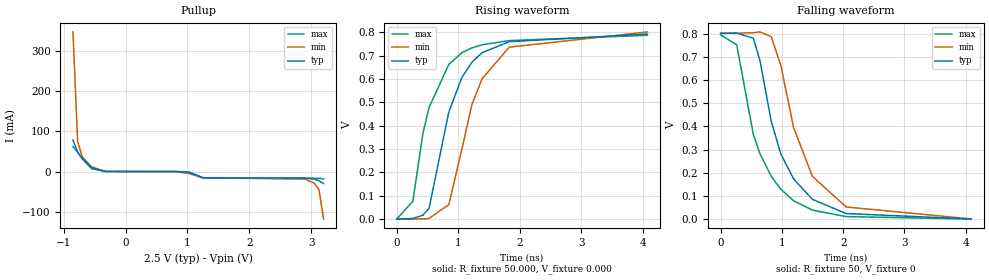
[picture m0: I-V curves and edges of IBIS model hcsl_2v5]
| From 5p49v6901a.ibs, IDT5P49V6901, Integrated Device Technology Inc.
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|   Model HCSL_2V5
[Model]   hcsl_2v5
Model_type   Open_source
Polarity   Non-Inverting
|   typ   min   max
C_comp   2pF   1.5pF   2.5pF
Vmeas = 0.43V
Rref = 50
Cref = 0
Vref = 0V
|   typ   min   max
[Voltage range]   2.5V   2.375V   2.625V
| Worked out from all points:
|   rising waveform, R_fixture 50.000, V_fixture 0.000: 20-80 % time 484ps typ, 517ps min, 446ps max; typ from 0 V to 0.793 V
|   falling waveform, R_fixture 50, V_fixture 0: 20-80 % time 553ps typ, 561ps min, 545ps max; typ from 0.802 V to 0 V
[Pullup]
|Voltage   I (typ)   I (min)   I (max)
|Note, modeling breaks down at 250mA and above.  This is well beyond the functional   |
|operating range of the device.  Should this scenario occur, catastrophic failure and   |
|possible damage to the device and/or board is of higher concern than the I-V curve   |
|behavior.  The IBIS checker will flag currents in excess of 10A with warnings.  Lines   |
|with currents in excess of 0.35 A have been commented out.  The points still remain|
|available to the user if the user desires to use them.   |
|-2.50000e+00   4.18820e+02   3.62831e+02   5.13988e+02
|-2.42500e+00   3.98060e+02   3.45526e+02   4.87489e+02
|-2.35000e+00   3.77301e+02   3.28221e+02   4.60992e+02
|-2.27500e+00   3.56544e+02   3.10918e+02   4.34497e+02
|-2.20000e+00   3.35789e+02   2.93617e+02   4.08003e+02
|-2.12500e+00   3.15035e+02   2.76317e+02   3.81510e+02
|-2.05000e+00   2.94284e+02   2.59020e+02   3.55019e+02
|-1.97500e+00   2.73534e+02   2.41725e+02   3.28531e+02
|-1.90000e+00   2.52787e+02   2.24432e+02   3.02045e+02
|-1.82500e+00   2.32043e+02   2.07143e+02   2.75561e+02
|-1.75000e+00   2.11303e+02   1.89857e+02   2.49081e+02
|-1.67500e+00   1.90567e+02   1.72576e+02   2.22604e+02
|-1.60000e+00   1.69836e+02   1.55301e+02   1.96133e+02
|-1.52500e+00   1.49113e+02   1.38033e+02   1.69668e+02
|-1.45000e+00   1.28399e+02   1.20775e+02   1.43213e+02
|-1.37500e+00   1.07699e+02   1.03530e+02   1.16771e+02
|-1.30000e+00   8.70206e+01   8.63041e+01   9.03510e+01
|-1.22500e+00   6.63754e+01   6.91071e+01   6.39696e+01
|-1.15000e+00   4.57798e+01   5.19493e+01   3.76540e+01
|-1.07500e+00   2.52424e+01   3.48371e+01   1.14171e+01
|-1.00000e+00   5.41544e+00   1.77617e+01   4.43906e-01
|-9.25000e-01   3.83575e-01   3.12352e+00   8.37580e-02
-850mV    78.22mA    346.9mA    62mA
-775mV    48.65mA    75.2mA     48.13mA
-700mV    32.45mA    36.4mA     31.33mA
-550mV    9.462mA    11.62mA    7.118mA
-325mV    90.12uA    245.7uA    48.7uA
800mV     13.39uA    -86.15uA   39.9uA
1.025V    -2.499mA   -4.68mA    -734.3uA
1.25V     -15.62mA   -15.74mA   -15.3mA
2.9V      -16.6mA    -18.65mA   -16.36mA
3.05V     -18.62mA   -28.95mA   -16.45mA
3.125V    -22.86mA   -44.46mA   -16.7mA
3.2V      -30mA      -118mA     -18.33mA
| 3.27500e+00   -3.99973e-02   -7.03299e-01   -2.35496e-02
| 3.35000e+00   -6.07334e-02   -6.06546e+00   -3.27185e-02
| 3.42500e+00   -2.19666e-01   -1.69043e+01   -4.43357e-02
| 3.50000e+00   -2.40671e+00   -2.77743e+01   -5.63861e-02
| 3.57500e+00   -1.44320e+01   -3.86883e+01   -8.58002e-02
| 3.65000e+00   -2.74894e+01   -4.96441e+01   -6.38151e-01
| 3.72500e+00   -4.06046e+01   -6.06330e+01   -1.12031e+01
| 3.80000e+00   -5.37689e+01   -7.16520e+01   -2.79002e+01
| 3.87500e+00   -6.69730e+01   -8.26854e+01   -4.46763e+01
| 3.95000e+00   -8.02022e+01   -9.37284e+01   -6.15101e+01
| 4.02500e+00   -9.34439e+01   -1.04778e+02   -7.83881e+01
| 4.10000e+00   -1.06694e+02   -1.15833e+02   -9.52824e+01
| 4.17500e+00   -1.19949e+02   -1.26892e+02   -1.12186e+02
| 4.25000e+00   -1.33208e+02   -1.37953e+02   -1.29096e+02
| 4.32500e+00   -1.46471e+02   -1.49017e+02   -1.46010e+02
| 4.40000e+00   -1.59735e+02   -1.60082e+02   -1.62927e+02
| 4.47500e+00   -1.73001e+02   -1.71149e+02   -1.79845e+02
| 4.55000e+00   -1.86268e+02   -1.82218e+02   -1.96764e+02
| 4.62500e+00   -1.99537e+02   -1.93287e+02   -2.13683e+02
| 4.70000e+00   -2.12805e+02   -2.04356e+02   -2.30604e+02
| 4.77500e+00   -2.26075e+02   -2.15427e+02   -2.47524e+02
| 4.85000e+00   -2.39344e+02   -2.26498e+02   -2.64445e+02
| 4.92500e+00   -2.52615e+02   -2.37569e+02   -2.81365e+02
| 5.00000e+00   -2.65885e+02   -2.48641e+02   -2.98285e+02
[Ramp]
|   typ   min   max
dV/dt_r   0.475/0.484n   0.476/0.517n   0.472/0.445n
dV/dt_f   0.484/0.553n   0.484/0.561n   0.48/0.544n
[Rising Waveform]
R_fixture = 50.000
V_fixture = 0.000
C_fixture = 0.000
|  time   V(typ)   V(min)   V(max)
|   0.0000S   28.5793nV   0.0000V   29.5095nV
|   2.3462pS   31.0738nV   2.4061nV   32.1138nV
|   4.2108pS   32.4562nV   3.7577nV   33.5300nV
|   4.4420pS   32.5955nV   3.8628nV   33.7030nV
|   7.3280pS   33.9249nV   5.0972nV   35.0261nV
|   13.0019pS   33.3378nV   5.1447nV   34.2093nV
|   13.6485pS   33.2990nV   5.3782nV   34.1032nV
|   25.3304pS   33.1176nV   11.3216nV   29.4633nV
|   37.2341pS   57.3045nV   49.6739nV   53.8500nV
|   44.0306pS   97.1087nV   71.5711nV   87.6653nV
|   53.3133pS   152.7020nV   131.3706nV   143.8910nV
|   60.9180pS   203.5620nV   167.5757nV   195.7820nV
|   70.0000pS   237.8080nV   183.2777nV   249.4730nV
|   72.5284pS   220.6020nV   141.6206nV   248.8590nV
|   76.7544pS   153.5140nV   41.9220nV   222.0950nV
|   78.9623pS   95.1189nV   -15.6849nV   195.6210nV
|   80.9324pS   41.4279nV   -87.5339nV   173.5600nV
|   88.5157pS   -148.9140nV   -304.8954nV   128.5840nV
|   93.1838pS   -107.4520nV   -417.7216nV   227.6830nV
|  101.7760pS   777.1820pV   -211.9427nV   448.4860nV
|  109.9270pS   525.8680nV   186.3348nV   871.3740nV
|  117.1110pS   1.0438uV   773.2547nV   1.2050uV
|  122.3270pS   1.4411uV   1.2347uV   1.3277uV
|  131.3260pS   1.7549uV   1.8623uV   1.4319uV
|  140.6930pS   1.7963uV   2.1994uV   1.1210uV
|  148.1030pS   1.4259uV   1.7308uV   152.7890nV
|  153.9250pS   164.2910nV   1.2348uV   -914.7540nV
|  167.5560pS   -4.6287uV   -2.8398uV   -6.3502uV
|  177.3450pS   -9.4856uV   -8.4278uV   -12.4768uV
|  187.4150pS   -16.4560uV   -14.4705uV   -19.4102uV
|  204.4310pS   -28.2434uV   -26.3360uV   -32.5150uV
|  216.2830pS   -36.4630uV   -34.0899uV   -40.9609uV
|  229.2050pS   -44.6579uV   -42.3338uV   -48.5451uV
|  243.7590pS   -52.7527uV   -50.0817uV   -54.4610uV
|  252.2000pS   -55.5125uV   -54.5752uV   -51.7248uV
|  259.2920pS   -55.5394uV   -56.2824uV   -47.0232uV
|  264.7700pS   -53.1141uV   -57.6011uV   -42.7650uV
|  275.8110pS   -47.2652uV   -54.9867uV   -35.0982uV
|  281.5050pS   -43.8840uV   -53.1142uV   -32.1211uV
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0s        28.58nV    0V         29.51nV
261.4ps   2.114mV    -121.9uV   76.3mV
424.2ps   16.32mV    209.7uV    366.2mV
525ps     45.74mV    2.661mV    477.8mV
846.1ps   458.7mV    61.44mV    662.7mV
1.06ns    607.4mV    300.7mV    713.4mV
1.221ns   671.6mV    489.5mV    733.6mV
1.387ns   713.2mV    601.4mV    747.2mV
1.83ns    760.5mV    737mV      765.2mV
4.077ns   793.1mV    802.2mV    787.8mV
[Falling Waveform]
R_fixture = 50
V_fixture = 0
C_fixture = 0.0p
| Time   typ   min   max
| 0.00000e+00   8.01941e-01   8.02942e-01   7.95708e-01
| 5.33133e-11   8.01942e-01   8.02943e-01   7.95709e-01
| 7.67544e-11   8.01942e-01   8.02943e-01   7.95710e-01
| 8.37028e-11   8.01941e-01   8.02941e-01   7.95708e-01
| 9.31838e-11   8.01937e-01   8.02938e-01   7.95705e-01
| 1.01776e-10   8.01934e-01   8.02934e-01   7.95701e-01
| 1.09927e-10   8.01931e-01   8.02931e-01   7.95697e-01
| 1.17111e-10   8.01928e-01   8.02929e-01   7.95694e-01
| 1.22327e-10   8.01927e-01   8.02928e-01   7.95692e-01
| 1.31326e-10   8.01924e-01   8.02925e-01   7.95689e-01
| 1.40693e-10   8.01921e-01   8.02923e-01   7.95686e-01
| 1.48103e-10   8.01919e-01   8.02921e-01   7.95682e-01
| 1.60973e-10   8.01912e-01   8.02915e-01   7.95674e-01
| 1.69673e-10   8.01905e-01   8.02909e-01   7.95668e-01
| 1.85089e-10   8.01891e-01   8.02896e-01   7.95652e-01
| 1.97157e-10   8.01879e-01   8.02884e-01   7.95640e-01
| 2.07668e-10   8.01870e-01   8.02874e-01   7.95631e-01
| 2.23901e-10   8.01858e-01   8.02862e-01   7.95619e-01
| 2.37017e-10   8.01850e-01   8.02854e-01   7.95618e-01
| 2.49663e-10   8.01846e-01   8.02848e-01   7.95623e-01
| 2.54056e-10   8.01848e-01   8.02847e-01   7.95626e-01
| 2.64416e-10   8.01854e-01   8.02847e-01   7.95641e-01
| 2.69451e-10   8.01859e-01   8.02849e-01   7.95648e-01
| 2.79424e-10   8.01870e-01   8.02855e-01   7.95662e-01
| 2.85315e-10   8.01877e-01   8.02861e-01   7.95669e-01
| 2.93370e-10   8.01886e-01   8.02869e-01   7.95679e-01
| 3.05155e-10   8.01900e-01   8.02881e-01   7.95691e-01
| 3.18179e-10   8.01914e-01   8.02894e-01   7.95703e-01
| 3.25707e-10   8.01921e-01   8.02902e-01   7.95709e-01
| 3.36176e-10   8.01931e-01   8.02912e-01   7.95715e-01
| 3.51299e-10   8.01942e-01   8.02926e-01   7.95722e-01
| 3.66584e-10   8.01951e-01   8.02938e-01   7.95727e-01
| 3.74935e-10   8.01956e-01   8.02944e-01   7.95729e-01
| 4.00361e-10   8.01965e-01   8.02958e-01   7.95735e-01
| 4.15457e-10   8.01969e-01   8.02965e-01   7.95739e-01
| 4.25576e-10   8.01972e-01   8.02969e-01   7.95741e-01
| 4.34776e-10   8.01975e-01   8.02972e-01   7.95744e-01
| 4.47976e-10   8.01979e-01   8.02977e-01   7.95747e-01
| 4.57169e-10   8.01982e-01   8.02980e-01   7.95748e-01
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0s        801.9mV    802.9mV    795.7mV
262.4ps   803.4mV    802.8mV    752.9mV
533.6ps   781.3mV    804.8mV    365.9mV
642ps     685.2mV    808.3mV    282.1mV
824.6ps   423.9mV    788.2mV    185.4mV
981.2ps   281.9mV    664.9mV    129.3mV
1.191ns   173.3mV    395.2mV    79.15mV
1.496ns   85.61mV    185.1mV    38.68mV
2.047ns   23.91mV    52.3mV     10.76mV
4.089ns   342.4uV    600.6uV    216.2uV
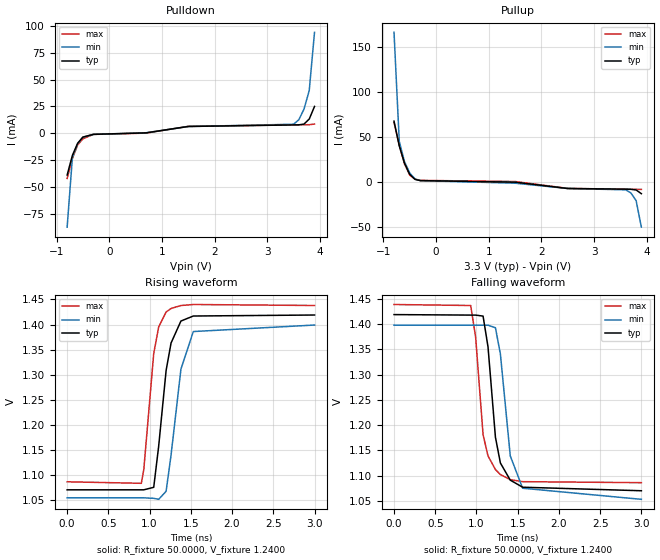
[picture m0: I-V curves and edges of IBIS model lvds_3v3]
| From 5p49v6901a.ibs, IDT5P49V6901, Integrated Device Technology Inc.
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[Model]   lvds_3v3
Model_type   Output
Polarity   Non-Inverting
|   typ   min   max
C_comp   2pF   1.5pF   2.5pF
Vmeas = 1.25V
Rref = 50
Cref = 2.0000pF
Vref = 1.25V
|   typ   min   max
[Voltage range]   3.3V   3.135V   3.465V
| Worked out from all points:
|   slope of the pulldown table from 0 to 0.495 V, typ, clamps not added: 1.35 kohm
|   slope of the pullup table from 0 to 0.495 V, typ, clamps not added: 2.31 kohm
|   rising waveform, R_fixture 50.0000, V_fixture 1.2400: 20-80 % time 141ps typ, 153ps min, 122ps max; typ from 1.07 V to 1.42 V
|   falling waveform, R_fixture 50.0000, V_fixture 1.2400: 20-80 % time 126ps typ, 138ps min, 116ps max; typ from 1.42 V to 1.07 V
[Pulldown]
|Voltage   I (typ)   I (min)   I (max)
|Note, modeling breaks down at 250mA and above.  This is well beyond the functional   |
|operating range of the device.  Should this scenario occur, catastrophic failure and   |
|possible damage to the device and/or board is of higher concern than the I-V curve   |
|behavior.  The IBIS checker will flag currents in excess of 10A with warnings.  Lines   |
|with currents in excess of 0.35 A have been commented out.  The points still remain|
|available to the user if the user desires to use them.   |
|  -3.30   -0.4582kA   -0.3985kA   -0.5583kA
|  -3.20   -0.4380kA   -0.3813kA   -0.5333kA
|  -3.10   -0.4179kA   -0.3641kA   -0.5083kA
|  -3.00   -0.3978kA   -0.3469kA   -0.4833kA
|  -2.90   -0.3776kA   -0.3297kA   -0.4583kA
|  -2.80   -0.3575kA   -0.3125kA   -0.4333kA
|  -2.70   -0.3374kA   -0.2954kA   -0.4083kA
|  -2.60   -0.3173kA   -0.2782kA   -0.3833kA
|  -2.50   -0.2972kA   -0.2611kA   -0.3584kA
|  -2.40   -0.2771kA   -0.2439kA   -0.3334kA
|  -2.30   -0.2570kA   -0.2268kA   -0.3084kA
|  -2.20   -0.2370kA   -0.2097kA   -0.2835kA
|  -2.10   -0.2169kA   -0.1926kA   -0.2585kA
|  -2.00   -0.1969kA   -0.1756kA   -0.2336kA
|  -1.90   -0.1769kA   -0.1585kA   -0.2087kA
|  -1.80   -0.1569kA   -0.1415kA   -0.1838kA
|  -1.70   -0.1370kA   -0.1246kA   -0.1590kA
|  -1.60   -0.1172kA   -0.1077kA   -0.1342kA
|  -1.50   -97.4500A   -91.0200A   -0.1095kA
|  -1.40   -77.8400A   -74.4200A   -84.9400A
|  -1.30   -58.5000A   -58.1100A   -60.6000A
|  -1.20   -39.6600A   -42.2500A   -36.8000A
|  -1.10   -21.5900A   -27.0400A   -13.9400A
|  -1.00   -4.1450A   -12.3600A   -0.3834A
|  -0.90   -0.1592A   -1.1570A   -64.1900mA
-800mV    -38.8mA    -87.29mA   -41.95mA
-700mV    -20.46mA   -22.38mA   -23.42mA
-600mV    -9.163mA   -9.47mA    -10.79mA
-500mV    -3.444mA   -3.582mA   -5.079mA
-300mV    -919.6uA   -946.5uA   -970.7uA
700mV     447.6uA    578.5uA    248.3uA
1.5V      6.423mA    6.34mA     6.53mA
3.5V      7.848mA    8.487mA    7.912mA
3.6V      7.922mA    12.55mA    7.955mA
3.7V      8.616mA    22.48mA    7.999mA
3.8V      13.34mA    39.88mA    8.057mA
3.9V      25.05mA    94.03mA    8.65mA
|  4.00   43.9800mA   0.8865A   14.2600mA
|  4.10   70.9600mA   13.8800A   28.7000mA
|  4.20   0.2968A   36.6400A   51.5700mA
|  4.30   8.8350A   59.4700A   74.7900mA
|  4.40   36.1700A   82.3700A   0.1211A
|  4.50   63.5900A   0.1053kA   3.5170A
|  4.60   91.1100A   0.1283kA   36.4900A
|  4.70   0.1187kA   0.1513kA   71.5800A
|  4.80   0.1463kA   0.1743kA   0.1067kA
|  4.90   0.1739kA   0.1974kA   0.1420kA
|  5.00   0.2015kA   0.2204kA   0.1773kA
|  5.10   0.2292kA   0.2435kA   0.2126kA
|  5.20   0.2569kA   0.2666kA   0.2479kA
|  5.30   0.2845kA   0.2896kA   0.2832kA
|  5.40   0.3122kA   0.3127kA   0.3185kA
|  5.50   0.3399kA   0.3358kA   0.3538kA
|  5.60   0.3676kA   0.3589kA   0.3891kA
|  5.70   0.3952kA   0.3819kA   0.4245kA
|  5.80   0.4229kA   0.4050kA   0.4598kA
|  5.90   0.4506kA   0.4281kA   0.4951kA
|  6.00   0.4783kA   0.4512kA   0.5305kA
|  6.10   0.5060kA   0.4743kA   0.5658kA
|  6.20   0.5337kA   0.4974kA   0.6012kA
|  6.30   0.5614kA   0.5205kA   0.6365kA
|  6.40   0.5891kA   0.5436kA   0.6719kA
|  6.50   0.6168kA   0.5667kA   0.7072kA
|  6.60   0.6445kA   0.5898kA   0.7425kA
[Pullup]
|Voltage   I (typ)   I (min)   I (max)
|Note, modeling breaks down at 250mA and above.  This is well beyond the functional   |
|operating range of the device.  Should this scenario occur, catastrophic failure and   |
|possible damage to the device and/or board is of higher concern than the I-V curve   |
|behavior.  The IBIS checker will flag currents in excess of 10A with warnings.  Lines   |
|with currents in excess of 0.35 A have been commented out.  The points still remain|
|available to the user if the user desires to use them.   |
|  -3.30   0.6445kA   0.5517kA   0.8009kA
|  -3.20   0.6168kA   0.5286kA   0.7655kA
|  -3.10   0.5891kA   0.5055kA   0.7302kA
|  -3.00   0.5614kA   0.4824kA   0.6948kA
|  -2.90   0.5337kA   0.4593kA   0.6595kA
|  -2.80   0.5060kA   0.4362kA   0.6241kA
|  -2.70   0.4783kA   0.4131kA   0.5888kA
|  -2.60   0.4506kA   0.3900kA   0.5535kA
|  -2.50   0.4229kA   0.3669kA   0.5181kA
|  -2.40   0.3953kA   0.3439kA   0.4828kA
|  -2.30   0.3676kA   0.3208kA   0.4474kA
|  -2.20   0.3399kA   0.2977kA   0.4121kA
|  -2.10   0.3122kA   0.2746kA   0.3768kA
|  -2.00   0.2845kA   0.2516kA   0.3415kA
|  -1.90   0.2569kA   0.2285kA   0.3061kA
|  -1.80   0.2292kA   0.2055kA   0.2708kA
|  -1.70   0.2016kA   0.1824kA   0.2355kA
|  -1.60   0.1739kA   0.1594kA   0.2002kA
|  -1.50   0.1463kA   0.1363kA   0.1649kA
|  -1.40   0.1187kA   0.1133kA   0.1296kA
|  -1.30   91.1200A   90.4000A   94.4500A
|  -1.20   63.5900A   67.4700A   59.2800A
|  -1.10   36.1700A   44.6200A   24.2500A
|  -1.00   8.8330A   21.8400A   0.7339A
|  -0.90   0.2942A   2.5180A   91.8900mA
-800mV    67.29mA    165.8mA    65.83mA
-700mV    39.75mA    44.68mA    40.36mA
-600mV    20.42mA    22.1mA     19.56mA
-500mV    8.108mA    9.559mA    7.259mA
-400mV    2.573mA    3.091mA    2.828mA
-300mV    1.267mA    1.258mA    1.499mA
1.5V      -484.3uA   -1.606mA   262.2uA
2.5V      -7.49mA    -7.515mA   -7.37mA
3.6V      -8.243mA   -8.947mA   -8.321mA
3.7V      -8.348mA   -12.35mA   -8.379mA
3.8V      -9.122mA   -20.94mA   -8.436mA
3.9V      -13.29mA   -50.39mA   -8.517mA
|  4.00   -23.0400mA   -0.4276A   -9.2430mA
|  4.10   -39.5300mA   -7.2910A   -14.5500mA
|  4.20   -0.1578A   -21.8600A   -27.4900mA
|  4.30   -4.1410A   -36.8500A   -44.1800mA
|  4.40   -21.5800A   -52.4900A   -76.1600mA
|  4.50   -39.6500A   -68.6700A   -1.6140A
|  4.60   -58.4900A   -85.1800A   -21.8200A
|  4.70   -77.8300A   -0.1018kA   -45.0300A
|  4.80   -97.4400A   -0.1187kA   -69.0600A
|  4.90   -0.1172kA   -0.1356kA   -93.5000A
|  5.00   -0.1370kA   -0.1526kA   -0.1181kA
|  5.10   -0.1569kA   -0.1696kA   -0.1428kA
|  5.20   -0.1769kA   -0.1866kA   -0.1677kA
|  5.30   -0.1969kA   -0.2037kA   -0.1925kA
|  5.40   -0.2169kA   -0.2208kA   -0.2174kA
|  5.50   -0.2370kA   -0.2379kA   -0.2423kA
|  5.60   -0.2570kA   -0.2550kA   -0.2672kA
|  5.70   -0.2771kA   -0.2722kA   -0.2922kA
|  5.80   -0.2972kA   -0.2893kA   -0.3171kA
|  5.90   -0.3173kA   -0.3065kA   -0.3421kA
|  6.00   -0.3374kA   -0.3237kA   -0.3671kA
|  6.10   -0.3575kA   -0.3409kA   -0.3921kA
|  6.20   -0.3776kA   -0.3580kA   -0.4170kA
|  6.30   -0.3977kA   -0.3752kA   -0.4420kA
|  6.40   -0.4179kA   -0.3924kA   -0.4670kA
|  6.50   -0.4380kA   -0.4096kA   -0.4920kA
|  6.60   -0.4581kA   -0.4268kA   -0.5170kA
[Ramp]
|   typ   min   max
dV/dt_r   0.21/0.14n   0.21/0.15n   0.22/0.128n
dV/dt_f   0.21/0.12n   0.21/0.14n   0.21/0.11n
R_load =   50
[Rising Waveform]
R_fixture= 50.0000
V_fixture= 1.2400
V_fixture_min= 1.2200
V_fixture_max= 1.2600
C_fixture = 0.000
|  time   V(typ)   V(min)   V(max)
0s        1.07V      1.054V     1.086V
900ps     1.07V      1.054V     1.083V
930ps     1.07V      1.054V     1.111V
1.05ns    1.075V     1.053V     1.342V
1.11ns    1.157V     1.051V     1.395V
1.2ns     1.308V     1.067V     1.425V
1.26ns    1.363V     1.139V     1.432V
1.38ns    1.407V     1.311V     1.438V
1.53ns    1.417V     1.386V     1.44V
3ns       1.419V     1.399V     1.438V
[Falling Waveform]
R_fixture= 50.0000
V_fixture= 1.2400
V_fixture_min= 1.2200
V_fixture_max= 1.2600
C_fixture = 0.000
|  time   V(typ)   V(min)   V(max)
0s        1.419V     1.398V     1.439V
930ps     1.418V     1.398V     1.437V
990ps     1.418V     1.398V     1.374V
1.08ns    1.416V     1.398V     1.181V
1.14ns    1.355V     1.398V     1.139V
1.23ns    1.176V     1.393V     1.112V
1.29ns    1.125V     1.341V     1.102V
1.41ns    1.091V     1.139V     1.092V
1.56ns    1.077V     1.075V     1.088V
3ns       1.07V      1.053V     1.086V
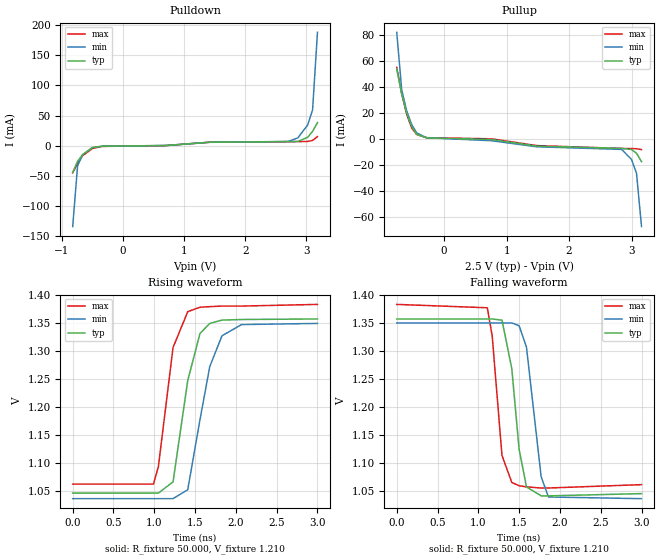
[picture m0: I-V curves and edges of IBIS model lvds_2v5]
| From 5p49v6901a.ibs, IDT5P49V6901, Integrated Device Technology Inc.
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[Model]   lvds_2v5
Model_type   Output
Polarity   Non-Inverting
|   typ   min   max
C_comp   2pF   1.5pF   2.5pF
Vmeas = 1.2V
Rref = 50
Cref = 2.0000pF
Vref = 1.2V
|   typ   min   max
[Voltage range]   2.5V   2.375V   2.625V
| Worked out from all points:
|   slope of the pulldown table from 0 to 0.375 V, typ, clamps not added: 2.21 kohm
|   slope of the pullup table from 0 to 0.375 V, typ, clamps not added: 2.23 kohm
|   rising waveform, R_fixture 50.000, V_fixture 1.210: 20-80 % time 196ps typ, 229ps min, 168ps max; typ from 1.05 V to 1.36 V
|   falling waveform, R_fixture 50.000, V_fixture 1.210: 20-80 % time 123ps typ, 144ps min, 107ps max; typ from 1.36 V to 1.05 V
[Pulldown]
|Voltage   I (typ)   I (min)   I (max)
|Note, modeling breaks down at 250mA and above.  This is well beyond the functional   |
|operating range of the device.  Should this scenario occur, catastrophic failure and   |
|possible damage to the device and/or board is of higher concern than the I-V curve   |
|behavior.  The IBIS checker will flag currents in excess of 10A with warnings.  Lines   |
|with currents in excess of 0.35 A have been commented out.  The points still remain|
|available to the user if the user desires to use them.   |
|  -2.50   -0.2972kA   -0.2611kA   -0.3583kA
|  -2.42   -0.2811kA   -0.2473kA   -0.3384kA
|  -2.34   -0.2651kA   -0.2336kA   -0.3184kA
|  -2.26   -0.2490kA   -0.2200kA   -0.2984kA
|  -2.18   -0.2330kA   -0.2063kA   -0.2785kA
|  -2.10   -0.2169kA   -0.1926kA   -0.2585kA
|  -2.02   -0.2009kA   -0.1790kA   -0.2386kA
|  -1.94   -0.1849kA   -0.1653kA   -0.2187kA
|  -1.86   -0.1689kA   -0.1517kA   -0.1987kA
|  -1.78   -0.1530kA   -0.1381kA   -0.1788kA
|  -1.70   -0.1370kA   -0.1246kA   -0.1590kA
|  -1.62   -0.1211kA   -0.1111kA   -0.1391kA
|  -1.54   -0.1053kA   -97.7000A   -0.1193kA
|  -1.46   -89.5800A   -84.3500A   -99.6600A
|  -1.38   -73.9400A   -71.1300A   -80.0400A
|  -1.30   -58.5000A   -58.1100A   -60.6000A
|  -1.22   -43.3700A   -45.3700A   -41.4900A
|  -1.14   -28.7200A   -33.0500A   -22.9700A
|  -1.06   -14.5400A   -21.1300A   -5.0190A
|  -0.98   -2.0260A   -9.4630A   -0.1959A
|  -0.90   -0.1583A   -1.1560A   -63.0600mA
-820mV    -44.36mA   -134mA     -44.88mA
-740mV    -26.03mA   -33.31mA   -29.63mA
-660mV    -14.78mA   -15.41mA   -16.81mA
-500mV    -3.134mA   -3.26mA    -4.727mA
-340mV    -851uA     -837.6uA   -1.156mA
700mV     355.5uA    317.2uA    190.7uA
1.42V     5.778mA    5.658mA    5.873mA
2.7V      6.77mA     7.054mA    6.772mA
2.86V     7.044mA    13.02mA    6.838mA
3.02V     13.95mA    34.37mA    7.04mA
3.1V      23.83mA    59.36mA    8.71mA
3.18V     38.32mA    188mA      15.18mA
|  3.26   57.3300mA   1.5990A   27.3600mA
|  3.34   93.9700mA   13.8800A   45.0100mA
|  3.42   0.5398A   32.0900A   64.8000mA
|  3.50   8.8330A   50.3300A   82.1900mA
|  3.58   30.6900A   68.6200A   0.1675A
|  3.66   52.6100A   86.9500A   3.5160A
|  3.74   74.5900A   0.1053kA   29.4900A
|  3.82   96.6300A   0.1237kA   57.5200A
|  3.90   0.1187kA   0.1421kA   85.6400A
|  3.98   0.1407kA   0.1605kA   0.1138kA
|  4.06   0.1628kA   0.1789kA   0.1420kA
|  4.14   0.1850kA   0.1974kA   0.1702kA
|  4.22   0.2071kA   0.2158kA   0.1984kA
|  4.30   0.2292kA   0.2343kA   0.2267kA
|  4.38   0.2513kA   0.2527kA   0.2549kA
|  4.46   0.2735kA   0.2712kA   0.2832kA
|  4.54   0.2956kA   0.2896kA   0.3114kA
|  4.62   0.3177kA   0.3081kA   0.3397kA
|  4.70   0.3399kA   0.3265kA   0.3679kA
|  4.78   0.3620kA   0.3450kA   0.3962kA
|  4.86   0.3842kA   0.3635kA   0.4245kA
|  4.94   0.4063kA   0.3819kA   0.4527kA
[Pullup]
|Voltage   I (typ)   I (min)   I (max)
|Note, modeling breaks down at 250mA and above.  This is well beyond the functional   |
|operating range of the device.  Should this scenario occur, catastrophic failure and   |
|possible damage to the device and/or board is of higher concern than the I-V curve   |
|behavior.  The IBIS checker will flag currents in excess of 10A with warnings.  Lines   |
|with currents in excess of 0.35 A have been commented out.  The points still remain|
|available to the user if the user desires to use them.   |
|  -2.44   0.4063kA   0.3531kA   0.4969kA
|  -2.36   0.3842kA   0.3346kA   0.4686kA
|  -2.28   0.3620kA   0.3162kA   0.4404kA
|  -2.20   0.3399kA   0.2977kA   0.4121kA
|  -2.12   0.3177kA   0.2793kA   0.3839kA
|  -2.04   0.2956kA   0.2608kA   0.3556kA
|  -1.96   0.2735kA   0.2423kA   0.3273kA
|  -1.88   0.2513kA   0.2239kA   0.2991kA
|  -1.80   0.2292kA   0.2055kA   0.2708kA
|  -1.72   0.2071kA   0.1870kA   0.2426kA
|  -1.64   0.1850kA   0.1686kA   0.2143kA
|  -1.56   0.1628kA   0.1502kA   0.1861kA
|  -1.48   0.1407kA   0.1317kA   0.1579kA
|  -1.40   0.1187kA   0.1133kA   0.1296kA
|  -1.32   96.6300A   94.9900A   0.1015kA
|  -1.24   74.5900A   76.6300A   73.3400A
|  -1.16   52.6100A   58.3200A   45.2500A
|  -1.08   30.6900A   40.0600A   17.2500A
|  -1.00   8.8320A   21.8400A   0.7328A
|  -0.92   0.5379A   4.6650A   0.1031A
|  -0.84   91.2400mA   0.4359A   73.7400mA
-760mV    53.9mA     82.15mA    55.12mA
-680mV    34.58mA    37.8mA     34.78mA
-600mV    19.77mA    21.51mA    18.87mA
-520mV    9.45mA     11.07mA    8.433mA
-440mV    3.57mA     4.621mA    3.384mA
-280mV    833.7uA    910.8uA    978.5uA
760mV     -398.9uA   -1.355mA   108.8uA
1.48V     -5.477mA   -6.046mA   -5.105mA
2.84V     -7.267mA   -8.038mA   -7.335mA
3V        -8.117mA   -15.75mA   -7.43mA
3.08V     -11.01mA   -26.46mA   -7.526mA
3.16V     -17.45mA   -67.48mA   -8.211mA
|  3.24   -27.5000mA   -0.4267A   -11.8300mA
|  3.32   -44.3500mA   -4.4170A   -20.4500mA
|  3.40   -0.1567A   -16.0000A   -33.0900mA
|  3.48   -2.0230A   -27.7800A   -46.5700mA
|  3.56   -14.5400A   -39.9200A   -75.1300mA
|  3.64   -28.7100A   -52.4900A   -0.6799A
|  3.72   -43.3600A   -65.4000A   -12.8100A
|  3.80   -58.4900A   -78.5400A   -30.9800A
|  3.88   -73.9400A   -91.8400A   -49.7800A
|  3.96   -89.5700A   -0.1052kA   -69.0600A
|  4.04   -0.1053kA   -0.1187kA   -88.5900A
|  4.12   -0.1211kA   -0.1322kA   -0.1082kA
|  4.20   -0.1370kA   -0.1458kA   -0.1280kA
|  4.28   -0.1529kA   -0.1594kA   -0.1478kA
|  4.36   -0.1689kA   -0.1730kA   -0.1676kA
|  4.44   -0.1849kA   -0.1866kA   -0.1875kA
|  4.52   -0.2009kA   -0.2003kA   -0.2074kA
|  4.60   -0.2169kA   -0.2140kA   -0.2273kA
|  4.68   -0.2329kA   -0.2276kA   -0.2473kA
|  4.76   -0.2490kA   -0.2413kA   -0.2672kA
|  4.84   -0.2650kA   -0.2550kA   -0.2872kA
|  4.92   -0.2811kA   -0.2688kA   -0.3071kA
|  5.00   -0.2972kA   -0.2825kA   -0.3271kA
[Ramp]
|   typ   min   max
dV/dt_r   0.19/0.198n   0.188/0.226n   0.188/0.167n
dV/dt_f   0.192/0.124n  0.194/0.147n   0.194/0.109n
R_load =   50
[Rising Waveform]
R_fixture = 50.000
V_fixture = 1.210
V_fixture_min = 1.190
V_fixture_max = 1.230
C_fixture = 0.000
|  time   V(typ)   V(min)   V(max)
0s        1.046V     1.036V     1.062V
990ps     1.046V     1.036V     1.062V
1.05ns    1.046V     1.036V     1.093V
1.23ns    1.066V     1.036V     1.306V
1.41ns    1.247V     1.052V     1.37V
1.56ns    1.331V     1.177V     1.378V
1.68ns    1.349V     1.272V     1.379V
1.83ns    1.355V     1.327V     1.38V
2.07ns    1.356V     1.347V     1.38V
3ns       1.357V     1.349V     1.383V
[Falling Waveform]
R_fixture = 50.000
V_fixture = 1.210
V_fixture_min = 1.190
V_fixture_max = 1.230
C_fixture = 0.000
|  time   V(typ)   V(min)   V(max)
0s        1.357V     1.35V      1.383V
1.11ns    1.357V     1.35V      1.377V
1.17ns    1.357V     1.35V      1.327V
1.29ns    1.355V     1.35V      1.114V
1.41ns    1.269V     1.35V      1.066V
1.5ns     1.125V     1.345V     1.06V
1.59ns    1.058V     1.307V     1.058V
1.77ns    1.042V     1.076V     1.056V
1.86ns    1.042V     1.04V      1.056V
3ns       1.046V     1.037V     1.062V
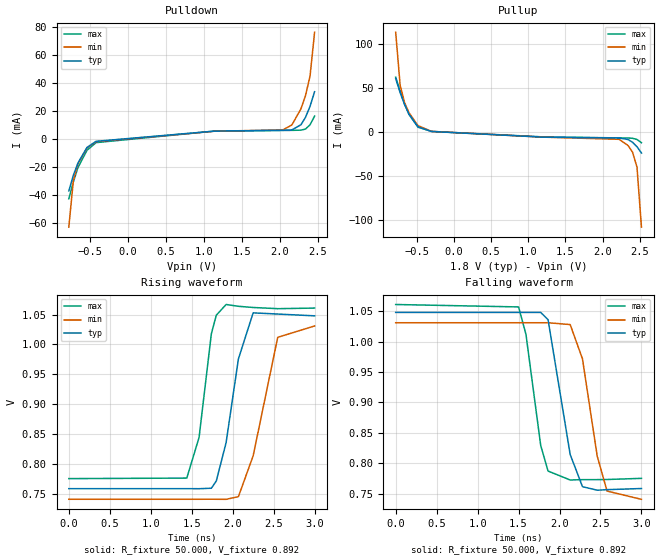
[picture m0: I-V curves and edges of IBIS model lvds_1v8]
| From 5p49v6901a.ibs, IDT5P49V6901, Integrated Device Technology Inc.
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[Model]   lvds_1v8
Model_type   Output
Polarity   Non-Inverting
|   typ   min   max
C_comp   2.0000pF   1.5000pF   2.5000pF
Vmeas =  0.9000V
Cref =   2.0000pF
Rref =   50.0000
Vref =   0.9000V
[Voltage Range]   1.8000V   1.7100V   1.8900V
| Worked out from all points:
|   slope of the pulldown table from 0 to 0.27 V, typ, clamps not added: 2.34 kohm
|   slope of the pullup table from 0 to 0.27 V, typ, clamps not added: 970 ohm
|   rising waveform, R_fixture 50.000, V_fixture 0.892: 20-80 % time 196ps typ, 247ps min, 153ps max; typ from 0.758 V to 1.05 V
|   falling waveform, R_fixture 50.000, V_fixture 0.892: 20-80 % time 183ps typ, 209ps min, 167ps max; typ from 1.05 V to 0.758 V
[Pulldown]
|Voltage   I(typ)   I(min)   I(max)
|Note, modeling breaks down at 250mA and above.  This is well beyond the functional   |
|operating range of the device.  Should this scenario occur, catastrophic failure and   |
|possible damage to the device and/or board is of higher concern than the I-V curve   |
|behavior.  The IBIS checker will flag currents in excess of 10A with warnings.  Lines   |
|with currents in excess of 0.35 A have been commented out.  The points still remain|
|available to the user if the user desires to use them.   |
|  -1.80   -0.1570kA   -0.1415kA   -0.1838kA
|  -1.74   -0.1450kA   -0.1314kA   -0.1689kA
|  -1.68   -0.1331kA   -0.1212kA   -0.1540kA
|  -1.62   -0.1211kA   -0.1111kA   -0.1392kA
|  -1.56   -0.1093kA   -0.1010kA   -0.1243kA
|  -1.50   -97.4600A   -91.0200A   -0.1095kA
|  -1.44   -85.6700A   -81.0400A   -94.7600A
|  -1.38   -73.9500A   -71.1400A   -80.0500A
|  -1.32   -62.3400A   -61.3500A   -65.4500A
|  -1.26   -50.8900A   -51.7000A   -51.0000A
|  -1.20   -39.6700A   -42.2600A   -36.8100A
|  -1.14   -28.7300A   -33.0500A   -22.9700A
|  -1.08   -18.0600A   -24.0800A   -9.4810A
|  -1.02   -7.5710A   -15.2800A   -0.8557A
|  -0.96   -1.0120A   -6.5720A   -0.1272A
|  -0.90   -0.1630A   -1.1600A   -69.8600mA
|  -0.84   -57.9600mA   -0.2220A   -54.8000mA
-780mV    -36.97mA   -62.75mA   -42.52mA
-720mV    -25.84mA   -29.43mA   -30.55mA
-660mV    -17.18mA   -17.75mA   -20.42mA
-540mV    -5.999mA   -6.454mA   -8.01mA
-420mV    -1.673mA   -1.886mA   -2.606mA
1.14V     5.583mA    5.506mA    5.585mA
2.04V     6.169mA    6.447mA    6.071mA
2.16V     6.42mA     9.934mA    6.116mA
2.28V     10.1mA     21.4mA     6.272mA
2.34V     15.35mA    30.81mA    7.057mA
2.4V      23.19mA    44.74mA    10.07mA
2.46V     33.62mA    75.87mA    16.26mA
|  2.52   46.6200mA   0.2091A   25.6700mA
|  2.58   62.2400mA   1.0230A   38.2000mA
|  2.64   93.2900mA   6.2830A   53.1600mA
|  2.70   0.2947A   19.5700A   67.2300mA
|  2.76   2.1550A   33.2200A   80.0900mA
|  2.82   14.2900A   46.9000A   0.1118A
|  2.88   30.6900A   60.6100A   0.4884A
|  2.94   47.1200A   74.3400A   6.9660A
|  3.00   63.5900A   88.1000A   27.7400A
|  3.06   80.0900A   0.1018kA   48.7500A
|  3.12   96.6200A   0.1156kA   69.8200A
|  3.18   0.1131kA   0.1294kA   90.9200A
|  3.24   0.1297kA   0.1432kA   0.1120kA
|  3.30   0.1463kA   0.1571kA   0.1332kA
|  3.36   0.1628kA   0.1709kA   0.1543kA
|  3.42   0.1794kA   0.1847kA   0.1755kA
|  3.48   0.1960kA   0.1985kA   0.1967kA
|  3.54   0.2126kA   0.2124kA   0.2178kA
|  3.60   0.2292kA   0.2262kA   0.2390kA
[Pullup]
|Voltage   I(typ)   I(min)   I(max)
|Note, modeling breaks down at 250mA and above.  This is well beyond the functional   |
|operating range of the device.  Should this scenario occur, catastrophic failure and   |
|possible damage to the device and/or board is of higher concern than the I-V curve   |
|behavior.  The IBIS checker will flag currents in excess of 10A with warnings.  Lines   |
|with currents in excess of 0.35 A have been commented out.  The points still remain|
|available to the user if the user desires to use them.   |
|  -1.80   0.2292kA   0.2055kA   0.2708kA
|  -1.74   0.2126kA   0.1916kA   0.2496kA
|  -1.68   0.1960kA   0.1778kA   0.2285kA
|  -1.62   0.1794kA   0.1640kA   0.2073kA
|  -1.56   0.1629kA   0.1502kA   0.1861kA
|  -1.50   0.1463kA   0.1363kA   0.1649kA
|  -1.44   0.1297kA   0.1225kA   0.1438kA
|  -1.38   0.1131kA   0.1087kA   0.1226kA
|  -1.32   96.6300A   94.9900A   0.1015kA
|  -1.26   80.1000A   81.2200A   80.3800A
|  -1.20   63.6000A   67.4700A   59.2900A
|  -1.14   47.1300A   53.7500A   38.2500A
|  -1.08   30.7000A   40.0600A   17.2600A
|  -1.02   14.2900A   26.3900A   1.7620A
|  -0.96   2.1570A   12.7400A   0.1929A
|  -0.90   0.2956A   2.5190A   94.2200mA
|  -0.84   93.1800mA   0.4375A   76.6300mA
-780mV    61.19mA    113.6mA    62.6mA
-720mV    44.92mA    53.18mA    46.62mA
-660mV    31.39mA    33.54mA    31.9mA
-600mV    20.42mA    22.01mA    20.1mA
-480mV    6.096mA    7.503mA    5.766mA
-300mV    903.7uA    986.2uA    939.5uA
1.2V      -5.591mA   -5.565mA   -5.291mA
2.22V     -6.556mA   -8.024mA   -6.442mA
2.34V     -8.282mA   -15.11mA   -6.542mA
2.4V      -11.35mA   -22.54mA   -6.848mA
2.46V     -16.49mA   -39.62mA   -8.208mA
2.52V     -23.64mA   -107.9mA   -11.96mA
|  2.58   -33.1500mA   -0.4889A   -18.6200mA
|  2.64   -52.3200mA   -2.8130A   -27.6700mA
|  2.70   -0.1556A   -10.9100A   -37.6600mA
|  2.76   -1.0030A   -19.6500A   -48.1000mA
|  2.82   -7.5600A   -28.5300A   -69.8800mA
|  2.88   -18.0500A   -37.6100A   -0.2588A
|  2.94   -28.7100A   -46.9400A   -3.1710A
|  3.00   -39.6500A   -56.4900A   -16.1700A
|  3.06   -50.8800A   -66.2100A   -29.8200A
|  3.12   -62.3300A   -76.0600A   -43.8400A
|  3.18   -73.9300A   -86.0100A   -58.1700A
|  3.24   -85.6500A   -96.0200A   -72.7100A
|  3.30   -97.4400A   -0.1060kA   -87.3700A
|  3.36   -0.1092kA   -0.1161kA   -0.1021kA
|  3.42   -0.1211kA   -0.1263kA   -0.1169kA
|  3.48   -0.1330kA   -0.1364kA   -0.1317kA
|  3.54   -0.1450kA   -0.1466kA   -0.1466kA
|  3.60   -0.1569kA   -0.1568kA   -0.1614kA
[Ramp]
|   typ   min   max
dV/dt_r   0.177/0.202n   0.180/0.241n   0.175/0.154n
dV/dt_f   0.181/0.183n   0.182/0.207n   0.177/0.169n
R_load =   50
[Rising Waveform]
R_fixture = 50.000
V_fixture = 0.892
V_fixture_min = 0.884
V_fixture_max = 0.895
C_fixture = 0.000
|  time   V(typ)   V(min)   V(max)
0s        758.4mV    740.6mV    775.2mV
1.44ns    758.4mV    740.6mV    776.1mV
1.59ns    758.3mV    740.6mV    844.2mV
1.74ns    759.1mV    740.7mV    1.018V
1.8ns     771.2mV    740.6mV    1.049V
1.92ns    835.5mV    740.5mV    1.067V
2.07ns    975.7mV    745mV      1.064V
2.25ns    1.053V     813.3mV    1.062V
2.55ns    1.051V     1.012V     1.06V
3ns       1.048V     1.031V     1.061V
[Falling Waveform]
R_fixture = 50.000
V_fixture = 0.892
V_fixture_min = 0.884
V_fixture_max = 0.895
C_fixture = 0.000
|  time   V(typ)   V(min)   V(max)
0s        1.048V     1.031V     1.061V
1.5ns     1.048V     1.031V     1.057V
1.59ns    1.048V     1.031V     1.012V
1.77ns    1.048V     1.031V     829.4mV
1.86ns    1.036V     1.031V     787.1mV
2.13ns    814.3mV    1.028V     772.4mV
2.28ns    761.4mV    971.6mV    773mV
2.46ns    755.6mV    811.6mV    773mV
2.58ns    756.5mV    754.2mV    773.2mV
3ns       758.4mV    740.6mV    775.1mV
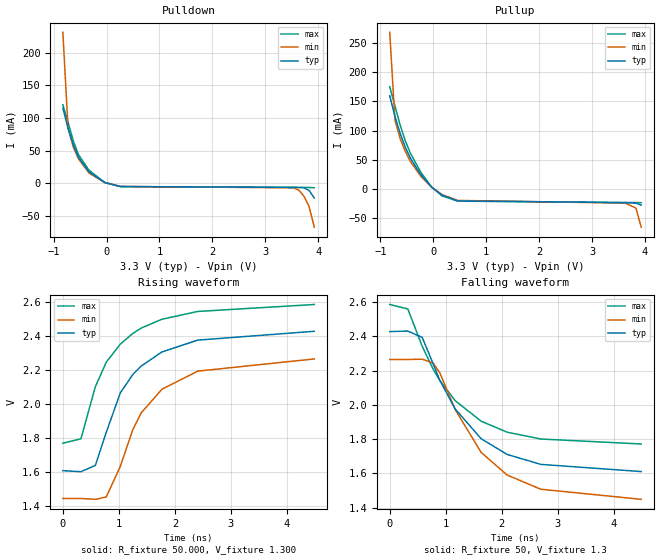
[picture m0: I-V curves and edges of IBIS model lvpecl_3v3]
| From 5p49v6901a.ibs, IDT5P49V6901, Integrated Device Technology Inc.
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[Model]   lvpecl_3v3
Model_type   Output_ECL
Polarity   Non-Inverting
|   typ   min   max
C_comp   2pF   1.5pF   2.5pF
Vmeas = 2.056V
Rref = 50
Cref = 0
Vref = 1.3V
|   typ   min   max
[Voltage range]   3.3V   3.135V   3.465V
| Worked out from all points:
|   rising waveform, R_fixture 50.000, V_fixture 1.300: 20-80 % time 834ps typ, 830ps min, 836ps max; typ from 1.61 V to 2.43 V
|   falling waveform, R_fixture 50, V_fixture 1.3: 20-80 % time 999ps typ, 993ps min, 1ns max; typ from 2.43 V to 1.61 V
[Pulldown]
|Voltage   I (typ)   I (min)   I (max)
|Note, modeling breaks down at 250mA and above.  This is well beyond the functional   |
|operating range of the device.  Should this scenario occur, catastrophic failure and   |
|possible damage to the device and/or board is of higher concern than the I-V curve   |
|behavior.  The IBIS checker will flag currents in excess of 10A with warnings.  Lines   |
|with currents in excess of 0.35 A have been commented out.  The points still remain|
|available to the user if the user desires to use them.   |
|-3.30000e+00   6.40494e+02   5.47645e+02   7.96897e+02
|-3.20100e+00   6.13071e+02   5.24782e+02   7.61900e+02
|-3.10200e+00   5.85650e+02   5.01920e+02   7.26904e+02
|-3.00300e+00   5.58231e+02   4.79060e+02   6.91910e+02
|-2.90400e+00   5.30813e+02   4.56202e+02   6.56917e+02
|-2.80500e+00   5.03397e+02   4.33346e+02   6.21926e+02
|-2.70600e+00   4.75983e+02   4.10491e+02   5.86937e+02
|-2.60700e+00   4.48571e+02   3.87639e+02   5.51949e+02
|-2.50800e+00   4.21161e+02   3.64788e+02   5.16964e+02
|-2.40900e+00   3.93753e+02   3.41940e+02   4.81981e+02
|-2.31000e+00   3.66348e+02   3.19095e+02   4.47000e+02
|-2.21100e+00   3.38946e+02   2.96252e+02   4.12022e+02
|-2.11200e+00   3.11546e+02   2.73413e+02   3.77047e+02
|-2.01300e+00   2.84151e+02   2.50577e+02   3.42075e+02
|-1.91400e+00   2.56759e+02   2.27746e+02   3.07106e+02
|-1.81500e+00   2.29372e+02   2.04920e+02   2.72143e+02
|-1.71600e+00   2.01992e+02   1.82101e+02   2.37185e+02
|-1.61700e+00   1.74621e+02   1.59291e+02   2.02236e+02
|-1.51800e+00   1.47261e+02   1.36492e+02   1.67297e+02
|-1.41900e+00   1.19919e+02   1.13712e+02   1.32374e+02
|-1.32000e+00   9.26062e+01   9.09588e+01   9.74818e+01
|-1.22100e+00   6.53450e+01   6.82506e+01   6.26476e+01
|-1.12200e+00   3.81712e+01   4.56115e+01   2.79291e+01
|-1.02300e+00   1.10897e+01   2.30475e+01   1.24893e+00
|-9.24000e-01   4.28238e-01   3.07704e+00   1.51169e-01
-825mV    115mA      231.1mA    120.2mA
-726mV    83.84mA    83.88mA    92.94mA
-627mV    58.71mA    55.32mA    64.83mA
-528mV    39.32mA    37.03mA    43.43mA
-330mV    17.18mA    15.49mA    19.86mA
-33mV     1.097mA    1.003mA    1.232mA
264mV     -5.075mA   -4.919mA   -5.211mA
3.531V    -6.413mA   -7.006mA   -6.366mA
3.63V     -6.463mA   -10.27mA   -6.395mA
3.729V    -6.98mA    -19.6mA    -6.428mA
3.828V    -10.89mA   -35.64mA   -6.475mA
3.927V    -22.76mA   -67.27mA   -6.885mA
| 4.02600e+00   -3.91581e-02   -5.27259e-01   -1.14674e-02
| 4.12500e+00   -5.19425e-02   -8.18306e+00   -2.73537e-02
| 4.22400e+00   -2.02189e-01   -2.24780e+01   -4.27150e-02
| 4.32300e+00   -5.36362e+00   -3.68412e+01   -5.54476e-02
| 4.42200e+00   -2.25356e+01   -5.12797e+01   -9.30834e-02
| 4.52100e+00   -3.98013e+01   -6.57781e+01   -2.39642e+00
| 4.62000e+00   -5.71554e+01   -8.03157e+01   -2.33704e+01
| 4.71900e+00   -7.45758e+01   -9.48736e+01   -4.54655e+01
| 4.81800e+00   -9.20266e+01   -1.09444e+02   -6.76653e+01
| 4.91700e+00   -1.09495e+02   -1.24024e+02   -8.99239e+01
| 5.01600e+00   -1.26974e+02   -1.38611e+02   -1.12205e+02
| 5.11500e+00   -1.44461e+02   -1.53203e+02   -1.34499e+02
| 5.21400e+00   -1.61953e+02   -1.67799e+02   -1.56802e+02
| 5.31300e+00   -1.79450e+02   -1.82398e+02   -1.79111e+02
| 5.41200e+00   -1.96951e+02   -1.97000e+02   -2.01425e+02
| 5.51100e+00   -2.14454e+02   -2.11605e+02   -2.23741e+02
| 5.61000e+00   -2.31959e+02   -2.26211e+02   -2.46061e+02
| 5.70900e+00   -2.49467e+02   -2.40819e+02   -2.68383e+02
| 5.80800e+00   -2.66976e+02   -2.55428e+02   -2.90706e+02
| 5.90700e+00   -2.84486e+02   -2.70039e+02   -3.13031e+02
| 6.00600e+00   -3.01998e+02   -2.84651e+02   -3.35358e+02
| 6.10500e+00   -3.19510e+02   -2.99263e+02   -3.57685e+02
| 6.20400e+00   -3.37024e+02   -3.13877e+02   -3.80013e+02
| 6.30300e+00   -3.54539e+02   -3.28492e+02   -4.02343e+02
| 6.40200e+00   -3.72054e+02   -3.43107e+02   -4.24672e+02
| 6.50100e+00   -3.89570e+02   -3.57723e+02   -4.47003e+02
| 6.60000e+00   -4.07087e+02   -3.72340e+02   -4.69334e+02
[Pullup]
|Voltage   I (typ)   I (min)   I (max)
|Note, modeling breaks down at 250mA and above.  This is well beyond the functional   |
|operating range of the device.  Should this scenario occur, catastrophic failure and   |
|possible damage to the device and/or board is of higher concern than the I-V curve   |
|behavior.  The IBIS checker will flag currents in excess of 10A with warnings.  Lines   |
|with currents in excess of 0.35 A have been commented out.  The points still remain|
|available to the user if the user desires to use them.   |
|-3.30000e+00   6.40605e+02   5.47748e+02   7.97022e+02
|-3.20100e+00   6.13181e+02   5.24884e+02   7.62023e+02
|-3.10200e+00   5.85758e+02   5.02020e+02   7.27026e+02
|-3.00300e+00   5.58337e+02   4.79159e+02   6.92030e+02
|-2.90400e+00   5.30918e+02   4.56298e+02   6.57035e+02
|-2.80500e+00   5.03500e+02   4.33440e+02   6.22043e+02
|-2.70600e+00   4.76084e+02   4.10583e+02   5.87053e+02
|-2.60700e+00   4.48670e+02   3.87728e+02   5.52065e+02
|-2.50800e+00   4.21258e+02   3.64876e+02   5.17079e+02
|-2.40900e+00   3.93848e+02   3.42025e+02   4.82094e+02
|-2.31000e+00   3.66441e+02   3.19177e+02   4.47112e+02
|-2.21100e+00   3.39037e+02   2.96332e+02   4.12132e+02
|-2.11200e+00   3.11636e+02   2.73490e+02   3.77154e+02
|-2.01300e+00   2.84238e+02   2.50652e+02   3.42180e+02
|-1.91400e+00   2.56844e+02   2.27819e+02   3.07209e+02
|-1.81500e+00   2.29455e+02   2.04990e+02   2.72242e+02
|-1.71600e+00   2.02072e+02   1.82169e+02   2.37281e+02
|-1.61700e+00   1.74697e+02   1.59355e+02   2.02328e+02
|-1.51800e+00   1.47334e+02   1.36554e+02   1.67385e+02
|-1.41900e+00   1.19989e+02   1.13771e+02   1.32459e+02
|-1.32000e+00   9.26721e+01   9.10147e+01   9.75623e+01
|-1.22100e+00   6.54071e+01   6.83032e+01   6.27235e+01
|-1.12200e+00   3.82293e+01   4.56605e+01   2.80002e+01
|-1.02300e+00   1.11435e+01   2.30929e+01   1.31491e+00
|-9.24000e-01   4.77531e-01   3.11851e+00   2.11788e-01
-825mV    159.6mA    268.6mA    175.1mA
-726mV    124mA      117.6mA    142.3mA
-627mV    94.83mA    85.82mA    109mA
-528mV    70.75mA    63.79mA    81.56mA
-429mV    51.56mA    46.15mA    60.02mA
-231mV    23.43mA    20.79mA    27.33mA
-33mV     2.74mA     2.456mA    3.148mA
165mV     -11.07mA   -10.12mA   -12.32mA
462mV     -20.83mA   -20.04mA   -21.28mA
3.63V     -23.8mA    -24.67mA   -23.68mA
3.828V    -24.79mA   -33.22mA   -23.76mA
3.927V    -28.03mA   -65.93mA   -23.85mA
| 4.02600e+00   -3.47525e-02   -5.27259e-01   -2.47658e-02
| 4.12500e+00   -5.19425e-02   -8.18306e+00   -2.89447e-02
| 4.22400e+00   -2.02189e-01   -2.24780e+01   -4.01130e-02
| 4.32300e+00   -5.36362e+00   -3.68412e+01   -5.54476e-02
| 4.42200e+00   -2.25356e+01   -5.12797e+01   -9.30837e-02
| 4.52100e+00   -3.98013e+01   -6.57781e+01   -2.39642e+00
| 4.62000e+00   -5.71554e+01   -8.03157e+01   -2.33704e+01
| 4.71900e+00   -7.45758e+01   -9.48736e+01   -4.54655e+01
| 4.81800e+00   -9.20266e+01   -1.09444e+02   -6.76653e+01
| 4.91700e+00   -1.09495e+02   -1.24024e+02   -8.99239e+01
| 5.01600e+00   -1.26974e+02   -1.38611e+02   -1.12205e+02
| 5.11500e+00   -1.44461e+02   -1.53203e+02   -1.34499e+02
| 5.21400e+00   -1.61953e+02   -1.67799e+02   -1.56802e+02
| 5.31300e+00   -1.79450e+02   -1.82398e+02   -1.79111e+02
| 5.41200e+00   -1.96951e+02   -1.97000e+02   -2.01425e+02
| 5.51100e+00   -2.14454e+02   -2.11605e+02   -2.23741e+02
| 5.61000e+00   -2.31959e+02   -2.26211e+02   -2.46061e+02
| 5.70900e+00   -2.49467e+02   -2.40819e+02   -2.68383e+02
| 5.80800e+00   -2.66976e+02   -2.55428e+02   -2.90706e+02
| 5.90700e+00   -2.84486e+02   -2.70039e+02   -3.13031e+02
| 6.00600e+00   -3.01998e+02   -2.84651e+02   -3.35358e+02
| 6.10500e+00   -3.19510e+02   -2.99263e+02   -3.57685e+02
| 6.20400e+00   -3.37024e+02   -3.13877e+02   -3.80013e+02
| 6.30300e+00   -3.54539e+02   -3.28492e+02   -4.02343e+02
| 6.40200e+00   -3.72054e+02   -3.43107e+02   -4.24672e+02
| 6.50100e+00   -3.89570e+02   -3.57723e+02   -4.47003e+02
| 6.60000e+00   -4.07087e+02   -3.72340e+02   -4.69334e+02
[Ramp]
|   typ   min   max
dV/dt_r   0.49/0.832n   0.49/0.83n   0.487/0.833n
dV/dt_f   0.492/0.998n   0.49/0.993n   0.492/1n
R_load =   50
[Rising Waveform]
R_fixture = 50.000
V_fixture = 1.300
V_fixture_min = 1.135
V_fixture_max = 1.465
C_fixture = 0.000
|  time   V(typ)   V(min)   V(max)
|   0.0000S   1.6060V   1.4423V   1.7683V
|   2.8363pS   1.6060V   1.4423V   1.7683V
|   5.2836pS   1.6060V   1.4423V   1.7683V
|   8.6600pS   1.6060V   1.4423V   1.7683V
|   15.6865pS   1.6060V   1.4423V   1.7683V
|   16.0689pS   1.6060V   1.4423V   1.7683V
|   29.7394pS   1.6060V   1.4423V   1.7683V
|   47.6708pS   1.6060V   1.4423V   1.7683V
|   50.2247pS   1.6060V   1.4423V   1.7683V
|   59.9282pS   1.6060V   1.4423V   1.7683V
|   70.0000pS   1.6060V   1.4423V   1.7683V
|   74.3341pS   1.6060V   1.4423V   1.7683V
|   79.7590pS   1.6060V   1.4423V   1.7683V
|   80.2022pS   1.6060V   1.4423V   1.7683V
|   84.9796pS   1.6060V   1.4423V   1.7683V
|   95.0261pS   1.6060V   1.4423V   1.7683V
|   96.2825pS   1.6060V   1.4423V   1.7683V
|  108.1050pS   1.6060V   1.4423V   1.7683V
|  116.6050pS   1.6060V   1.4423V   1.7683V
|  122.3340pS   1.6060V   1.4423V   1.7683V
|  131.2110pS   1.6060V   1.4423V   1.7683V
|  141.4880pS   1.6060V   1.4423V   1.7683V
|  150.7030pS   1.6060V   1.4423V   1.7683V
|  156.9780pS   1.6060V   1.4423V   1.7683V
|  172.1500pS   1.6060V   1.4423V   1.7683V
|  182.0970pS   1.6060V   1.4423V   1.7683V
|  194.7250pS   1.6060V   1.4423V   1.7683V
|  210.3500pS   1.6060V   1.4423V   1.7683V
|  230.0940pS   1.6060V   1.4423V   1.7682V
|  238.3070pS   1.6060V   1.4423V   1.7682V
|  251.5980pS   1.6060V   1.4423V   1.7682V
|  260.6170pS   1.6060V   1.4423V   1.7683V
|  269.7440pS   1.6060V   1.4423V   1.7683V
|  274.0000pS   1.6060V   1.4423V   1.7683V
|  285.3290pS   1.6060V   1.4423V   1.7683V
|  295.8940pS   1.6060V   1.4423V   1.7683V
|  299.8350pS   1.6060V   1.4423V   1.7683V
|  314.1120pS   1.6060V   1.4423V   1.7683V
|  325.8960pS   1.6060V   1.4423V   1.7683V
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0s        1.606V     1.442V     1.768V
322.8ps   1.6V       1.442V     1.794V
580ps     1.637V     1.437V     2.101V
775.7ps   1.833V     1.451V     2.246V
1.025ns   2.064V     1.631V     2.352V
1.248ns   2.173V     1.847V     2.415V
1.399ns   2.223V     1.947V     2.447V
1.768ns   2.306V     2.086V     2.499V
2.408ns   2.376V     2.193V     2.545V
4.489ns   2.428V     2.265V     2.586V
[Falling Waveform]
R_fixture = 50
V_fixture = 1.3   |Vcc_typ
V_fixture_min = 1.135 |Vcc_min
V_fixture_max = 1.465 |Vcc_max
C_fixture = 0.0p
| Time   typ   min   max
| 0.00000e+00   2.42830e+00   2.26498e+00   2.58589e+00
| 2.83628e-12   2.42830e+00   2.26498e+00   2.58589e+00
| 5.28355e-12   2.42830e+00   2.26498e+00   2.58589e+00
| 8.66002e-12   2.42830e+00   2.26498e+00   2.58589e+00
| 1.56865e-11   2.42830e+00   2.26498e+00   2.58589e+00
| 1.60689e-11   2.42830e+00   2.26498e+00   2.58589e+00
| 2.97394e-11   2.42830e+00   2.26498e+00   2.58589e+00
| 4.76708e-11   2.42830e+00   2.26498e+00   2.58589e+00
| 5.02247e-11   2.42830e+00   2.26498e+00   2.58589e+00
| 5.99282e-11   2.42830e+00   2.26498e+00   2.58589e+00
| 7.00000e-11   2.42830e+00   2.26498e+00   2.58589e+00
| 7.43341e-11   2.42830e+00   2.26498e+00   2.58589e+00
| 7.97590e-11   2.42830e+00   2.26498e+00   2.58589e+00
| 8.02022e-11   2.42830e+00   2.26498e+00   2.58589e+00
| 8.49796e-11   2.42830e+00   2.26498e+00   2.58589e+00
| 9.50261e-11   2.42829e+00   2.26497e+00   2.58589e+00
| 9.62825e-11   2.42829e+00   2.26497e+00   2.58589e+00
| 1.08105e-10   2.42829e+00   2.26497e+00   2.58588e+00
| 1.16605e-10   2.42828e+00   2.26497e+00   2.58588e+00
| 1.22334e-10   2.42828e+00   2.26497e+00   2.58587e+00
| 1.31211e-10   2.42828e+00   2.26496e+00   2.58587e+00
| 1.41488e-10   2.42828e+00   2.26496e+00   2.58587e+00
| 1.50703e-10   2.42828e+00   2.26496e+00   2.58587e+00
| 1.56978e-10   2.42828e+00   2.26496e+00   2.58586e+00
| 1.72150e-10   2.42827e+00   2.26495e+00   2.58586e+00
| 1.82097e-10   2.42826e+00   2.26495e+00   2.58585e+00
| 1.94725e-10   2.42825e+00   2.26494e+00   2.58584e+00
| 2.10350e-10   2.42824e+00   2.26493e+00   2.58583e+00
| 2.30094e-10   2.42824e+00   2.26492e+00   2.58583e+00
| 2.38307e-10   2.42823e+00   2.26492e+00   2.58583e+00
| 2.51598e-10   2.42823e+00   2.26491e+00   2.58583e+00
| 2.60617e-10   2.42824e+00   2.26491e+00   2.58584e+00
| 2.69744e-10   2.42824e+00   2.26492e+00   2.58585e+00
| 2.74000e-10   2.42825e+00   2.26492e+00   2.58585e+00
| 2.85329e-10   2.42825e+00   2.26492e+00   2.58586e+00
| 2.95894e-10   2.42826e+00   2.26493e+00   2.58587e+00
| 2.99835e-10   2.42826e+00   2.26493e+00   2.58587e+00
| 3.14112e-10   2.42827e+00   2.26494e+00   2.58588e+00
| 3.25896e-10   2.42828e+00   2.26495e+00   2.58588e+00
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0s        2.428V     2.265V     2.586V
322.8ps   2.431V     2.265V     2.56V
580ps     2.394V     2.267V     2.342V
775.7ps   2.239V     2.244V     2.208V
891.7ps   2.145V     2.189V     2.144V
1.167ns   1.977V     1.974V     2.025V
1.631ns   1.803V     1.723V     1.905V
2.095ns   1.711V     1.591V     1.841V
2.696ns   1.653V     1.508V     1.801V
4.488ns   1.611V     1.449V     1.772V
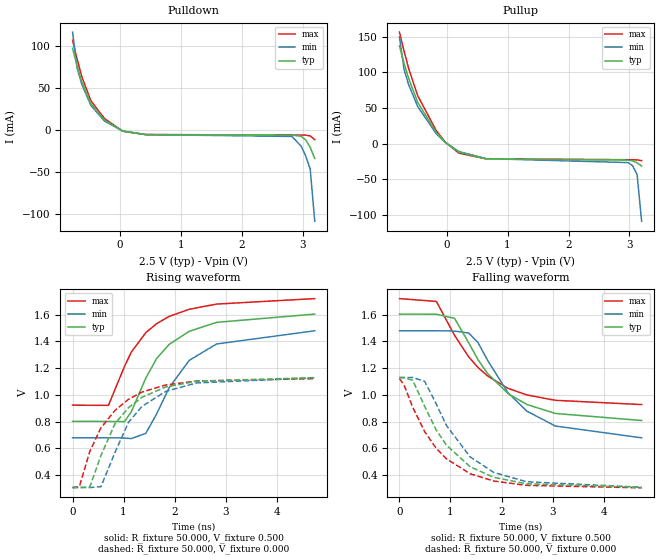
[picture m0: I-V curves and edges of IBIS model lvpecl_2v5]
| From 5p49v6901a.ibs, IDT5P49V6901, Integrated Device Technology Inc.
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[Model]   lvpecl_2v5
Model_type   Output_ECL
Polarity   Non-Inverting
|   typ   min   max
C_comp   2pF   1.5pF   2.5pF
Vmeas = 1.232V
Rref = 50
Cref = 0
Vref = 0.5V
|   typ   min   max
[Voltage range]   2.5V   2.375V   2.625V
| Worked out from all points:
|   rising waveform, R_fixture 50.000, V_fixture 0.500: 20-80 % time 874ps typ, 877ps min, 871ps max; typ from 0.801 V to 1.6 V
|   falling waveform, R_fixture 50.000, V_fixture 0.500: 20-80 % time 1.01ns typ, 1.01ns min, 1.01ns max; typ from 1.6 V to 0.808 V
|   rising waveform, R_fixture 50.000, V_fixture 0.000: 20-80 % time 795ps typ, 783ps min, 807ps max; typ from 0.306 V to 1.13 V
|   falling waveform, R_fixture 50.000, V_fixture 0.000: 20-80 % time 903ps typ, 912ps min, 896ps max; typ from 1.13 V to 0.307 V
[Pulldown]
|Voltage   I (typ)   I (min)   I (max)
|Note, modeling breaks down at 250mA and above.  This is well beyond the functional   |
|operating range of the device.  Should this scenario occur, catastrophic failure and   |
|possible damage to the device and/or board is of higher concern than the I-V curve   |
|behavior.  The IBIS checker will flag currents in excess of 10A with warnings.  Lines   |
|with currents in excess of 0.35 A have been commented out.  The points still remain|
|available to the user if the user desires to use them.   |
|-2.50000e+00   4.18945e+02   3.62941e+02   5.14135e+02
|-2.42500e+00   3.98182e+02   3.45632e+02   4.87633e+02
|-2.35000e+00   3.77420e+02   3.28324e+02   4.61132e+02
|-2.27500e+00   3.56659e+02   3.11018e+02   4.34632e+02
|-2.20000e+00   3.35900e+02   2.93713e+02   4.08134e+02
|-2.12500e+00   3.15143e+02   2.76411e+02   3.81638e+02
|-2.05000e+00   2.94388e+02   2.59110e+02   3.55143e+02
|-1.97500e+00   2.73635e+02   2.41812e+02   3.28651e+02
|-1.90000e+00   2.52885e+02   2.24517e+02   3.02161e+02
|-1.82500e+00   2.32138e+02   2.07225e+02   2.75673e+02
|-1.75000e+00   2.11394e+02   1.89936e+02   2.49189e+02
|-1.67500e+00   1.90655e+02   1.72652e+02   2.22709e+02
|-1.60000e+00   1.69921e+02   1.55374e+02   1.96234e+02
|-1.52500e+00   1.49195e+02   1.38103e+02   1.69766e+02
|-1.45000e+00   1.28478e+02   1.20842e+02   1.43307e+02
|-1.37500e+00   1.07775e+02   1.03595e+02   1.16861e+02
|-1.30000e+00   8.70930e+01   8.63664e+01   9.04378e+01
|-1.22500e+00   6.64446e+01   6.91666e+01   6.40526e+01
|-1.15000e+00   4.58458e+01   5.20061e+01   3.77333e+01
|-1.07500e+00   2.53052e+01   3.48910e+01   1.14925e+01
|-1.00000e+00   5.47493e+00   1.78128e+01   5.15481e-01
|-9.25000e-01   4.39708e-01   3.17173e+00   1.51366e-01
|-8.50000e-01   1.30875e-01   3.92096e-01   1.25523e-01
-775mV    97.45mA    116.9mA    107.2mA
-700mV    76.42mA    73.96mA    84.65mA
-625mV    57.99mA    54.67mA    64.03mA
-475mV    31.27mA    29.31mA    34.88mA
-250mV    11.68mA    10.49mA    13.45mA
50mV      -1.424mA   -1.32mA    -1.566mA
425mV     -5.587mA   -5.604mA   -5.525mA
2.825V    -6.213mA   -7.791mA   -6.123mA
2.975V    -7.55mA    -19.26mA   -6.147mA
3.05V     -11.81mA   -30.77mA   -6.236mA
3.125V    -20.86mA   -46.71mA   -7.118mA
3.2V      -34.07mA   -109.1mA   -11.66mA
| 3.27500e+00   -4.28591e-02   -6.77497e-01   -2.29449e-02
| 3.35000e+00   -5.93687e-02   -6.02030e+00   -3.77032e-02
| 3.42500e+00   -2.06550e-01   -1.68399e+01   -4.58101e-02
| 3.50000e+00   -2.37201e+00   -2.76912e+01   -5.67315e-02
| 3.57500e+00   -1.43732e+01   -3.85871e+01   -8.40584e-02
| 3.65000e+00   -2.74074e+01   -4.95256e+01   -6.20234e-01
| 3.72500e+00   -4.05002e+01   -6.04981e+01   -1.11551e+01
| 3.80000e+00   -5.36431e+01   -7.15014e+01   -2.78218e+01
| 3.87500e+00   -6.68269e+01   -8.25199e+01   -4.45692e+01
| 3.95000e+00   -8.00368e+01   -9.35488e+01   -6.13756e+01
| 4.02500e+00   -9.32604e+01   -1.04585e+02   -7.82275e+01
| 4.10000e+00   -1.06493e+02   -1.15628e+02   -9.50973e+01
| 4.17500e+00   -1.19733e+02   -1.26675e+02   -1.11978e+02
| 4.25000e+00   -1.32977e+02   -1.37726e+02   -1.28867e+02
| 4.32500e+00   -1.46226e+02   -1.48779e+02   -1.45761e+02
| 4.40000e+00   -1.59478e+02   -1.59836e+02   -1.62659e+02
| 4.47500e+00   -1.72732e+02   -1.70894e+02   -1.79560e+02
| 4.55000e+00   -1.85988e+02   -1.81954e+02   -1.96464e+02
| 4.62500e+00   -1.99247e+02   -1.93016e+02   -2.13369e+02
| 4.70000e+00   -2.12506e+02   -2.04079e+02   -2.30277e+02
| 4.77500e+00   -2.25768e+02   -2.15143e+02   -2.47185e+02
| 4.85000e+00   -2.39030e+02   -2.26208e+02   -2.64095e+02
| 4.92500e+00   -2.52293e+02   -2.37275e+02   -2.81007e+02
| 5.00000e+00   -2.65557e+02   -2.48342e+02   -2.97919e+02
[Pullup]
|Voltage   I (typ)   I (min)   I (max)
|Note, modeling breaks down at 250mA and above.  This is well beyond the functional   |
|operating range of the device.  Should this scenario occur, catastrophic failure and   |
|possible damage to the device and/or board is of higher concern than the I-V curve   |
|behavior.  The IBIS checker will flag currents in excess of 10A with warnings.  Lines   |
|with currents in excess of 0.35 A have been commented out.  The points still remain|
|available to the user if the user desires to use them.   |
|-2.50000e+00   4.19034e+02   3.63020e+02   5.14242e+02
|-2.42500e+00   3.98270e+02   3.45709e+02   4.87739e+02
|-2.35000e+00   3.77507e+02   3.28400e+02   4.61237e+02
|-2.27500e+00   3.56745e+02   3.11092e+02   4.34736e+02
|-2.20000e+00   3.35985e+02   2.93786e+02   4.08237e+02
|-2.12500e+00   3.15226e+02   2.76482e+02   3.81739e+02
|-2.05000e+00   2.94470e+02   2.59180e+02   3.55243e+02
|-1.97500e+00   2.73715e+02   2.41880e+02   3.28748e+02
|-1.90000e+00   2.52963e+02   2.24583e+02   3.02256e+02
|-1.82500e+00   2.32214e+02   2.07289e+02   2.75767e+02
|-1.75000e+00   2.11469e+02   1.89999e+02   2.49281e+02
|-1.67500e+00   1.90728e+02   1.72714e+02   2.22798e+02
|-1.60000e+00   1.69992e+02   1.55434e+02   1.96321e+02
|-1.52500e+00   1.49263e+02   1.38161e+02   1.69850e+02
|-1.45000e+00   1.28544e+02   1.20898e+02   1.43388e+02
|-1.37500e+00   1.07838e+02   1.03648e+02   1.16939e+02
|-1.30000e+00   8.71540e+01   8.64175e+01   9.05130e+01
|-1.22500e+00   6.65029e+01   6.92154e+01   6.41246e+01
|-1.15000e+00   4.59012e+01   5.20524e+01   3.78019e+01
|-1.07500e+00   2.53577e+01   3.49349e+01   1.15576e+01
|-1.00000e+00   5.52446e+00   1.78541e+01   5.76941e-01
|-9.25000e-01   4.86082e-01   3.21033e+00   2.08996e-01
|-8.50000e-01   1.73956e-01   4.27919e-01   1.79125e-01
-775mV    137.1mA    149.9mA    156.6mA
-700mV    113.1mA    104.5mA    130.2mA
-625mV    91.8mA     82.96mA    105.8mA
-475mV    57.93mA    51.98mA    67.24mA
-175mV    16.11mA    14.27mA    18.8mA
-25mV     1.95mA     1.743mA    2.247mA
200mV     -12.12mA   -11.08mA   -13.46mA
650mV     -21.54mA   -21.17mA   -21.49mA
2.975V    -23.12mA   -26.68mA   -22.66mA
3.05V     -24.26mA   -30.83mA   -22.68mA
3.125V    -26.94mA   -43.3mA    -22.85mA
3.2V      -31.52mA   -109.1mA   -23.95mA
| 3.27500e+00   -4.14121e-02   -6.77497e-01   -2.71789e-02
| 3.35000e+00   -5.93687e-02   -6.02030e+00   -3.32855e-02
| 3.42500e+00   -2.06550e-01   -1.68399e+01   -4.58101e-02
| 3.50000e+00   -2.37201e+00   -2.76912e+01   -5.67315e-02
| 3.57500e+00   -1.43732e+01   -3.85871e+01   -8.40584e-02
| 3.65000e+00   -2.74074e+01   -4.95256e+01   -6.20234e-01
| 3.72500e+00   -4.05002e+01   -6.04981e+01   -1.11551e+01
| 3.80000e+00   -5.36431e+01   -7.15014e+01   -2.78218e+01
| 3.87500e+00   -6.68269e+01   -8.25199e+01   -4.45692e+01
| 3.95000e+00   -8.00368e+01   -9.35488e+01   -6.13756e+01
| 4.02500e+00   -9.32604e+01   -1.04585e+02   -7.82275e+01
| 4.10000e+00   -1.06493e+02   -1.15628e+02   -9.50973e+01
| 4.17500e+00   -1.19733e+02   -1.26675e+02   -1.11978e+02
| 4.25000e+00   -1.32977e+02   -1.37726e+02   -1.28867e+02
| 4.32500e+00   -1.46226e+02   -1.48779e+02   -1.45761e+02
| 4.40000e+00   -1.59478e+02   -1.59836e+02   -1.62659e+02
| 4.47500e+00   -1.72732e+02   -1.70894e+02   -1.79560e+02
| 4.55000e+00   -1.85988e+02   -1.81954e+02   -1.96464e+02
| 4.62500e+00   -1.99247e+02   -1.93016e+02   -2.13369e+02
| 4.70000e+00   -2.12506e+02   -2.04079e+02   -2.30277e+02
| 4.77500e+00   -2.25768e+02   -2.15143e+02   -2.47185e+02
| 4.85000e+00   -2.39030e+02   -2.26208e+02   -2.64095e+02
| 4.92500e+00   -2.52293e+02   -2.37275e+02   -2.81007e+02
| 5.00000e+00   -2.65557e+02   -2.48342e+02   -2.97919e+02
[Ramp]
|   typ   min   max
dV/dt_r   0.479/0.874n   0.477/0.878n   0.478/0.87n
dV/dt_f   0.477/1.01n   0.474/1.007n   0.476/1.011n
R_load =   50
[Rising Waveform]
R_fixture = 50.000
V_fixture = 0.500
V_fixture_min = 0.375
V_fixture_max = 0.625
C_fixture = 0.000
|  time   V(typ)   V(min)   V(max)
|   0.0000S   801.3588mV   678.2443mV   922.6409mV
|   2.4688pS   801.3588mV   678.2443mV   922.6409mV
|   4.5531pS   801.3588mV   678.2443mV   922.6409mV
|   7.5237pS   801.3588mV   678.2443mV   922.6409mV
|   13.6989pS   801.3588mV   678.2443mV   922.6409mV
|   14.0263pS   801.3588mV   678.2443mV   922.6409mV
|   26.0494pS   801.3588mV   678.2443mV   922.6409mV
|   37.7325pS   801.3588mV   678.2443mV   922.6409mV
|   44.4264pS   801.3588mV   678.2443mV   922.6409mV
|   53.4388pS   801.3588mV   678.2443mV   922.6419mV
|   61.1399pS   801.3588mV   678.2443mV   922.6419mV
|   70.0000pS   801.3588mV   678.2443mV   922.6419mV
|   72.5018pS   801.3588mV   678.2443mV   922.6419mV
|   76.7279pS   801.3588mV   678.2443mV   922.6419mV
|   79.0571pS   801.3588mV   678.2443mV   922.6419mV
|   80.7859pS   801.3588mV   678.2443mV   922.6419mV
|   88.4406pS   801.3588mV   678.2433mV   922.6409mV
|   93.2133pS   801.3588mV   678.2433mV   922.6419mV
|  101.5460pS   801.3588mV   678.2443mV   922.6419mV
|  109.8730pS   801.3588mV   678.2443mV   922.6419mV
|  117.5110pS   801.3598mV   678.2443mV   922.6419mV
|  122.1580pS   801.3598mV   678.2453mV   922.6419mV
|  131.3390pS   801.3598mV   678.2453mV   922.6419mV
|  140.7040pS   801.3598mV   678.2453mV   922.6419mV
|  148.3010pS   801.3588mV   678.2443mV   922.6409mV
|  154.9730pS   801.3578mV   678.2443mV   922.6399mV
|  168.9430pS   801.3537mV   678.2402mV   922.6348mV
|  177.5100pS   801.3496mV   678.2362mV   922.6308mV
|  187.3800pS   801.3455mV   678.2321mV   922.6257mV
|  204.3880pS   801.3374mV   678.2239mV   922.6176mV
|  216.4710pS   801.3323mV   678.2188mV   922.6125mV
|  231.3170pS   801.3262mV   678.2137mV   922.6084mV
|  243.7050pS   801.3232mV   678.2097mV   922.6064mV
|  254.0000pS   801.3222mV   678.2076mV   922.6104mV
|  259.4880pS   801.3232mV   678.2066mV   922.6145mV
|  268.9240pS   801.3283mV   678.2076mV   922.6206mV
|  275.7510pS   801.3313mV   678.2097mV   922.6236mV
|  282.9450pS   801.3354mV   678.2127mV   922.6267mV
|  293.6130pS   801.3394mV   678.2168mV   922.6287mV
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0s        801.4mV    678.2mV    922.6mV
702.4ps   800.4mV    678.3mV    920.7mV
1.017ns   799.3mV    676.2mV    1.212V
1.152ns   873.2mV    672.3mV    1.321V
1.435ns   1.125V     711.1mV    1.466V
1.647ns   1.272V     857mV      1.533V
1.894ns   1.378V     1.054V     1.588V
2.286ns   1.476V     1.258V     1.641V
2.822ns   1.543V     1.381V     1.68V
4.746ns   1.605V     1.48V      1.721V
[Falling Waveform]
R_fixture = 50.000
V_fixture = 0.500
V_fixture_min = 0.375
V_fixture_max = 0.625
C_fixture = 0.000
|  time   V(typ)   V(min)   V(max)
|   0.0000S   1.6045V   1.4800V   1.7208V
|   2.4688pS   1.6045V   1.4800V   1.7208V
|   4.5531pS   1.6045V   1.4800V   1.7208V
|   7.5237pS   1.6045V   1.4800V   1.7208V
|   13.6989pS   1.6045V   1.4800V   1.7208V
|   14.0263pS   1.6045V   1.4800V   1.7208V
|   26.0494pS   1.6045V   1.4800V   1.7208V
|   37.7325pS   1.6045V   1.4800V   1.7208V
|   44.4264pS   1.6045V   1.4800V   1.7208V
|   53.4388pS   1.6045V   1.4800V   1.7208V
|   61.1399pS   1.6045V   1.4800V   1.7208V
|   70.0000pS   1.6045V   1.4800V   1.7208V
|   72.5018pS   1.6045V   1.4800V   1.7208V
|   76.7279pS   1.6045V   1.4800V   1.7208V
|   79.0571pS   1.6045V   1.4800V   1.7208V
|   80.7859pS   1.6045V   1.4800V   1.7208V
|   88.4406pS   1.6045V   1.4800V   1.7208V
|   93.2133pS   1.6045V   1.4800V   1.7208V
|  101.5460pS   1.6045V   1.4800V   1.7208V
|  109.8730pS   1.6045V   1.4800V   1.7208V
|  117.5110pS   1.6045V   1.4800V   1.7208V
|  122.1580pS   1.6045V   1.4800V   1.7208V
|  131.3390pS   1.6045V   1.4800V   1.7208V
|  140.7040pS   1.6045V   1.4800V   1.7208V
|  148.3010pS   1.6045V   1.4800V   1.7208V
|  154.9730pS   1.6045V   1.4800V   1.7208V
|  168.9430pS   1.6044V   1.4800V   1.7208V
|  177.5100pS   1.6044V   1.4800V   1.7207V
|  187.3800pS   1.6044V   1.4800V   1.7207V
|  204.3880pS   1.6044V   1.4800V   1.7207V
|  216.4710pS   1.6044V   1.4800V   1.7207V
|  231.3170pS   1.6044V   1.4800V   1.7207V
|  243.7050pS   1.6044V   1.4800V   1.7207V
|  254.0000pS   1.6044V   1.4800V   1.7207V
|  259.4880pS   1.6044V   1.4800V   1.7207V
|  268.9240pS   1.6044V   1.4800V   1.7207V
|  275.7510pS   1.6044V   1.4800V   1.7208V
|  282.9450pS   1.6044V   1.4800V   1.7208V
|  293.6130pS   1.6044V   1.4800V   1.7208V
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0s        1.605V     1.48V      1.721V
723.9ps   1.604V     1.48V      1.7V
1.081ns   1.573V     1.478V     1.445V
1.358ns   1.389V     1.463V     1.284V
1.539ns   1.264V     1.392V     1.205V
1.727ns   1.16V      1.259V     1.142V
2.126ns   1.01V      1.016V     1.049V
2.495ns   928.1mV    878.7mV    999.7mV
3.054ns   860.8mV    766.7mV    959.2mV
4.746ns   808mV      678.2mV    927.2mV
[Rising Waveform]
R_fixture = 50.000
V_fixture = 0.000
C_fixture = 0.000
|  time   V(typ)   V(min)   V(max)
|   0.0000S   305.8260mV   306.7900mV   302.9820mV
|  637.3320pS   305.8260mV   306.7900mV   302.9840mV
|  669.8800pS   305.8260mV   306.7900mV   302.9860mV
|  703.3130pS   305.8260mV   306.7900mV   302.9860mV
|  726.4910pS   305.8270mV   306.7900mV   302.9850mV
|  748.3920pS   305.8280mV   306.7900mV   302.9840mV
|  772.7480pS   305.8290mV   306.7900mV   302.9820mV
|  801.0220pS   305.8300mV   306.7900mV   302.9800mV
|  825.2090pS   305.8290mV   306.7910mV   302.9740mV
|  838.5260pS   305.8290mV   306.7910mV   302.9730mV
|  850.9620pS   305.8290mV   306.7920mV   302.9770mV
|  868.2170pS   305.8280mV   306.7920mV   302.9950mV
|  881.7090pS   305.8270mV   306.7930mV   303.0210mV
|  901.0030pS   305.8260mV   306.7930mV   303.0720mV
|  909.8110pS   305.8260mV   306.7930mV   303.0810mV
|  924.5770pS   305.8240mV   306.7930mV   303.0720mV
|  932.0620pS   305.8230mV   306.7930mV   303.0340mV
|  940.0850pS   305.8220mV   306.7930mV   302.9490mV
|  951.7060pS   305.8190mV   306.7930mV   302.6400mV
|  958.1260pS   305.8180mV   306.7930mV   302.3820mV
|  970.2040pS   305.8180mV   306.7930mV   301.8900mV
|  979.4410pS   305.8170mV   306.7920mV   301.5430mV
|  988.4070pS   305.8170mV   306.7900mV   301.2270mV
|   1.0037nS   305.8260mV   306.7880mV   300.7170mV
|   1.0131nS   305.8320mV   306.7870mV   300.4120mV
|   1.0345nS   305.8550mV   306.7830mV   299.7510mV
|   1.0464nS   305.8760mV   306.7820mV   299.3970mV
|   1.0669nS   305.9090mV   306.7810mV   298.8070mV
|   1.0745nS   305.9190mV   306.7810mV   298.5930mV
|   1.0909nS   305.8960mV   306.7810mV   298.1330mV
|   1.1007nS   305.8600mV   306.7810mV   297.7940mV
|   1.1090nS   305.7950mV   306.7810mV   297.5060mV
|   1.1190nS   305.6520mV   306.7820mV   296.6520mV
|   1.1281nS   305.4220mV   306.7830mV   295.8700mV
|   1.1324nS   305.2990mV   306.7840mV   295.6850mV
|   1.1449nS   304.9450mV   306.7890mV   295.1470mV
|   1.1555nS   304.6620mV   306.7940mV   297.0790mV
|   1.1641nS   304.4430mV   306.7990mV   298.6450mV
|   1.1791nS   304.0700mV   306.8100mV   306.3950mV
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0s        305.8mV    306.8mV    303mV
133.1ps   303.9mV    306.8mV    311.6mV
339ps     310.5mV    304.8mV    577.3mV
556ps     544.8mV    311.7mV    752.5mV
833ps     785.1mV    569.7mV    884.1mV
1.096ns   903.7mV    793.9mV    966.4mV
1.363ns   982.1mV    914mV      1.021V
1.827ns   1.059V     1.026V     1.074V
2.43ns    1.102V     1.089V     1.103V
4.746ns   1.129V     1.128V     1.121V
[Falling Waveform]
R_fixture = 50.000
V_fixture = 0.000
C_fixture = 0.000
|  time   V(typ)   V(min)   V(max)
|   0.0000S   1.1297V   1.1295V   1.1220V
|  850.9620pS   1.1297V   1.1295V   1.1219V
|  881.7090pS   1.1297V   1.1295V   1.1219V
|  924.5770pS   1.1297V   1.1295V   1.1220V
|  939.5140pS   1.1297V   1.1295V   1.1220V
|  945.8700pS   1.1297V   1.1295V   1.1221V
|  956.9460pS   1.1297V   1.1295V   1.1223V
|  965.0000pS   1.1297V   1.1295V   1.1224V
|  971.7860pS   1.1297V   1.1295V   1.1225V
|  988.0580pS   1.1297V   1.1295V   1.1226V
|  999.2290pS   1.1296V   1.1295V   1.1226V
|   1.0110nS   1.1296V   1.1295V   1.1227V
|   1.0284nS   1.1296V   1.1295V   1.1224V
|   1.0397nS   1.1296V   1.1295V   1.1215V
|   1.0549nS   1.1296V   1.1295V   1.1194V
|   1.0683nS   1.1296V   1.1295V   1.1166V
|   1.0824nS   1.1296V   1.1295V   1.1114V
|   1.0930nS   1.1297V   1.1295V   1.1071V
|   1.1013nS   1.1297V   1.1295V   1.1026V
|   1.1114nS   1.1297V   1.1295V   1.0967V
|   1.1262nS   1.1299V   1.1295V   1.0866V
|   1.1314nS   1.1300V   1.1295V   1.0828V
|   1.1395nS   1.1300V   1.1295V   1.0766V
|   1.1469nS   1.1301V   1.1295V   1.0707V
|   1.1595nS   1.1301V   1.1295V   1.0599V
|   1.1658nS   1.1301V   1.1295V   1.0544V
|   1.1833nS   1.1302V   1.1295V   1.0382V
|   1.1964nS   1.1302V   1.1295V   1.0249V
|   1.2124nS   1.1299V   1.1295V   1.0088V
|   1.2366nS   1.1286V   1.1295V   983.4050mV
|   1.2456nS   1.1275V   1.1295V   973.9020mV
|   1.2547nS   1.1264V   1.1295V   964.5040mV
|   1.2642nS   1.1247V   1.1295V   955.1750mV
|   1.2868nS   1.1192V   1.1296V   932.8110mV
|   1.2877nS   1.1189V   1.1296V   931.9450mV
|   1.3042nS   1.1124V   1.1297V   916.3320mV
|   1.3136nS   1.1087V   1.1297V   907.5250mV
|   1.3283nS   1.1010V   1.1298V   893.6010mV
|   1.3383nS   1.0957V   1.1298V   884.8600mV
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0s        1.13V      1.129V     1.122V
93.24ps   1.13V      1.129V     1.071V
259.9ps   1.109V     1.13V      907.5mV
495.9ps   913.1mV    1.101V     723.7mV
716ps     740mV      936.3mV    602.1mV
920ps     623.4mV    771.2mV    521.3mV
1.386ns   461.5mV    534.9mV    408.8mV
1.85ns    382.1mV    419mV      354.5mV
2.49ns    334.2mV    349.1mV    322mV
4.746ns   306.7mV    308.1mV    303.6mV
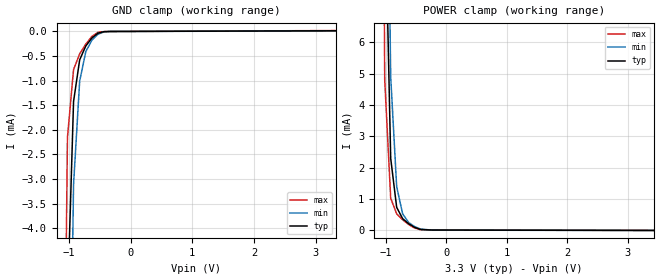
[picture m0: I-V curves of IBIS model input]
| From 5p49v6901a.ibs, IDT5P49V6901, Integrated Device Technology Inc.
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[Model]   input
Model_type   Input
Polarity   Non-Inverting
Enable   Active-High
Vinl = 0.8V
Vinh = 2.0V
|   typ   min   max
C_comp   2pF   1.5pF   2.5pF
|   typ   min   max
[Voltage range]   3.3V   3.135V   3.465V
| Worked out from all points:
|   GND clamp passes 1 mA (typ) near -0.87 V on its own axis
|   POWER clamp passes 1 mA (typ) near -0.84 V on its own axis
[GND_clamp]
|Voltage   I (typ)   I (min)   I (max)
-3.3V     -5.877A    -5.408A    -6.492A
-1.122V   -26.71mA   -42.1mA    -13.37mA
-1.023V   -5.55mA    -11.5mA    -2.155mA
-924mV    -1.425mA   -3.112mA   -776.1uA
-825mV    -579.5uA   -1.011mA   -457.9uA
-726mV    -298.2uA   -414.7uA   -259.6uA
-627mV    -135.7uA   -178.7uA   -102.9uA
-528mV    -37.47uA   -59.22uA   -19.83uA
-429mV    -6.866uA   -11.92uA   -5.643uA
-330mV    -3.062uA   -3.056uA   -3.933uA
3.333V    11.06uA    8.259uA    15.61uA
| 3.43200e+00   1.10646e-05   9.85198e-06   1.56123e-05
| 3.46500e+00   1.10748e-05   1.56686e-05   1.56145e-05
| 3.53100e+00   1.10953e-05   2.73017e-05   1.56184e-05
| 3.63000e+00   1.22240e-05   9.00221e-05   1.56239e-05
| 3.72900e+00   2.94089e-05   2.01383e-04   1.56343e-05
| 3.82800e+00   9.82853e-05   4.04552e-04   1.61859e-05
| 3.92700e+00   2.13921e-04   9.74740e-04   3.14030e-05
| 4.02600e+00   3.75114e-04   3.15078e-03   1.08238e-04
| 4.12500e+00   7.35643e-04   1.23144e-02   2.36650e-04
| 4.22400e+00   2.30231e-03   4.64533e-02   3.97348e-04
| 4.32300e+00   1.10342e-02   1.34572e-01   6.21132e-04
| 4.42200e+00   5.26801e-02   2.82717e-01   1.53968e-03
| 4.52100e+00   1.68112e-01   4.72773e-01   9.44647e-03
| 4.62000e+00   3.53430e-01   6.87934e-01   6.47105e-02
| 4.71900e+00   5.79768e-01   9.19142e-01   2.25514e-01
| 4.81800e+00   8.28544e-01   1.16053e+00   4.62411e-01
| 4.91700e+00   1.09117e+00   1.40901e+00   7.35436e-01
| 5.01600e+00   1.36245e+00   1.66266e+00   1.02689e+00
| 5.11500e+00   1.63974e+00   1.92021e+00   1.32900e+00
| 5.21400e+00   1.92140e+00   2.18081e+00   1.63813e+00
| 5.31300e+00   2.20638e+00   2.44384e+00   1.95201e+00
| 5.41200e+00   2.49395e+00   2.70886e+00   2.26936e+00
| 5.51100e+00   2.78359e+00   2.97552e+00   2.58936e+00
| 5.61000e+00   3.07492e+00   3.24357e+00   2.91142e+00
| 5.70900e+00   3.36767e+00   3.51280e+00   3.23516e+00
| 5.80800e+00   3.66160e+00   3.78306e+00   3.56026e+00
| 5.90700e+00   3.95656e+00   4.05420e+00   3.88650e+00
| 6.00600e+00   4.25239e+00   4.32613e+00   4.21370e+00
| 6.10500e+00   4.54899e+00   4.59875e+00   4.54174e+00
| 6.20400e+00   4.84627e+00   4.87198e+00   4.87049e+00
| 6.30300e+00   5.14414e+00   5.14577e+00   5.19987e+00
| 6.40200e+00   5.44256e+00   5.42005e+00   5.52980e+00
| 6.50100e+00   5.74145e+00   5.69479e+00   5.86022e+00
| 6.60000e+00   6.04077e+00   5.96994e+00   6.19109e+00
[Power_clamp]
|Voltage   I (typ)   I (min)   I (max)
-3.3V     6.041A     5.512A     6.743A
-1.122V   52.68mA    68.73mA    36.05mA
-1.023V   11.03mA    19.49mA    4.811mA
-924mV    2.302mA    4.908mA    1.028mA
-825mV    735.6uA    1.396mA    528.4uA
-726mV    375.1uA    526.2uA    340.6uA
-627mV    213.9uA    252.9uA    189.6uA
-528mV    98.2uA     121.6uA    75.41uA
-429mV    29.41uA    42.52uA    21.55uA
-231mV    11.1uA     8.404uA    15.63uA
3.432V    -1.145uA   -2.375uA   378.6nA
